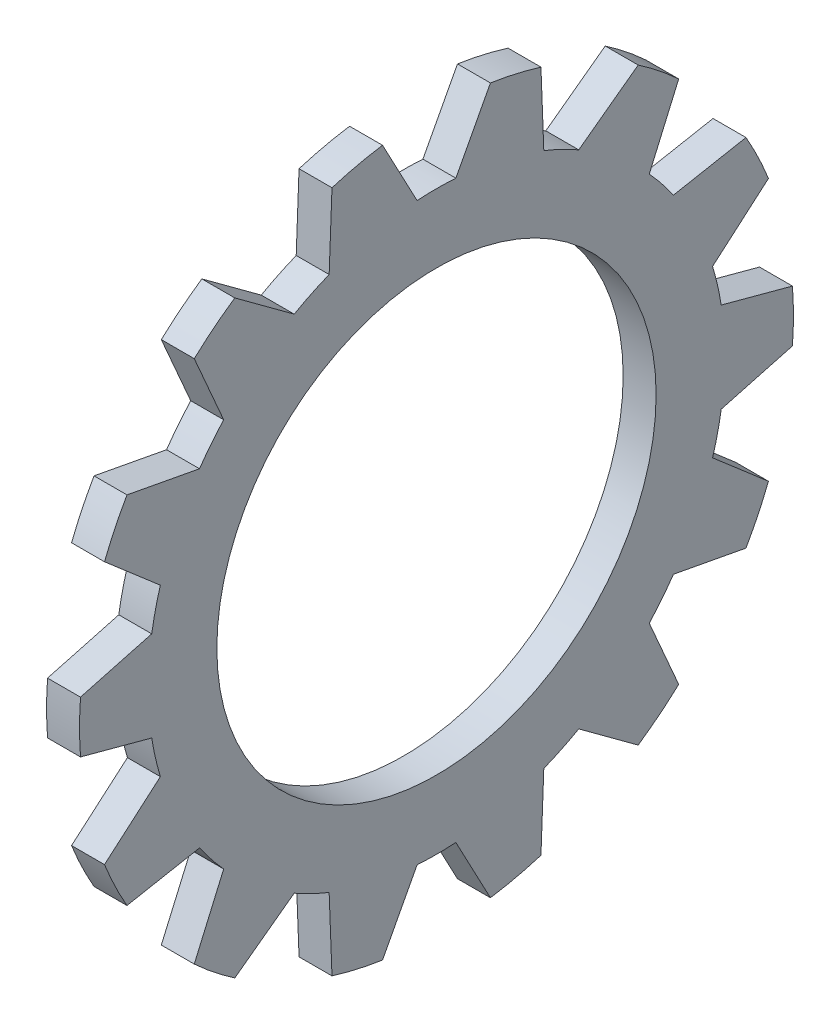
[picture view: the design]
ISO-10303-21;
HEADER;
FILE_DESCRIPTION(('STEP AP214'),'2;1');
FILE_NAME('part.step','',(''),(''),'','','');
FILE_SCHEMA(('AUTOMOTIVE_DESIGN { 1 0 10303 214 1 1 1 1 }'));
ENDSEC;
DATA;
#1=APPLICATION_CONTEXT('core data for automotive mechanical design processes');
#2=APPLICATION_PROTOCOL_DEFINITION('international standard','automotive_design',2000,#1);
#3=PRODUCT_CONTEXT('',#1,'mechanical');
#4=PRODUCT('Part','Part','',(#3));
#5=PRODUCT_RELATED_PRODUCT_CATEGORY('part','',(#4));
#6=PRODUCT_DEFINITION_FORMATION('','',#4);
#7=PRODUCT_DEFINITION_CONTEXT('part definition',#1,'design');
#8=PRODUCT_DEFINITION('design','',#6,#7);
#9=PRODUCT_DEFINITION_SHAPE('','',#8);
#10=(LENGTH_UNIT() NAMED_UNIT(*) SI_UNIT(.MILLI.,.METRE.));
#11=(NAMED_UNIT(*) PLANE_ANGLE_UNIT() SI_UNIT($,.RADIAN.));
#12=(NAMED_UNIT(*) SI_UNIT($,.STERADIAN.) SOLID_ANGLE_UNIT());
#13=UNCERTAINTY_MEASURE_WITH_UNIT(LENGTH_MEASURE(1.E-05),#10,'distance_accuracy_value','');
#14=(GEOMETRIC_REPRESENTATION_CONTEXT(3) GLOBAL_UNCERTAINTY_ASSIGNED_CONTEXT((#13)) GLOBAL_UNIT_ASSIGNED_CONTEXT((#10,
#11,#12)) REPRESENTATION_CONTEXT('',''));
#15=CARTESIAN_POINT('',(0.,0.,0.));
#16=DIRECTION('',(0.,0.,1.));
#17=DIRECTION('',(1.,0.,0.));
#18=AXIS2_PLACEMENT_3D('',#15,#16,#17);
#19=CARTESIAN_POINT('',(-34.9249999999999,0.,0.));
#20=DIRECTION('',(-1.,0.,0.));
#21=DIRECTION('',(0.,0.,1.));
#22=AXIS2_PLACEMENT_3D('',#19,#20,#21);
#23=CYLINDRICAL_SURFACE('',#22,13.);
#24=CARTESIAN_POINT('',(-1.2,0.,0.));
#25=DIRECTION('',(-1.,0.,0.));
#26=DIRECTION('',(0.,0.,1.));
#27=AXIS2_PLACEMENT_3D('',#24,#25,#26);
#28=CIRCLE('',#27,13.);
#29=CARTESIAN_POINT('',(-1.2,9.54851327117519,8.82189856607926));
#30=VERTEX_POINT('',#29);
#31=CARTESIAN_POINT('',(-1.2,10.7254592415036,7.34605499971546));
#32=VERTEX_POINT('',#31);
#33=EDGE_CURVE('E754',#30,#32,#28,.T.);
#34=ORIENTED_EDGE('',*,*,#33,.F.);
#35=DIRECTION('',(-1.,0.,0.));
#36=VECTOR('',#35,1.);
#37=CARTESIAN_POINT('',(-34.9249999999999,9.54851327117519,8.82189856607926));
#38=LINE('',#37,#36);
#39=CARTESIAN_POINT('',(0.,9.54851327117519,8.82189856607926));
#40=VERTEX_POINT('',#39);
#41=EDGE_CURVE('E686',#30,#40,#38,.F.);
#42=ORIENTED_EDGE('',*,*,#41,.T.);
#43=CARTESIAN_POINT('',(0.,0.,0.));
#44=DIRECTION('',(-1.,0.,0.));
#45=DIRECTION('',(0.,0.,1.));
#46=AXIS2_PLACEMENT_3D('',#43,#44,#45);
#47=CIRCLE('',#46,13.);
#48=CARTESIAN_POINT('',(0.,10.7254592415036,7.34605499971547));
#49=VERTEX_POINT('',#48);
#50=EDGE_CURVE('E748',#40,#49,#47,.T.);
#51=ORIENTED_EDGE('',*,*,#50,.T.);
#52=DIRECTION('',(-1.,0.,0.));
#53=VECTOR('',#52,1.);
#54=CARTESIAN_POINT('',(-34.9249999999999,10.7254592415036,7.34605499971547));
#55=LINE('',#54,#53);
#56=EDGE_CURVE('E706',#49,#32,#55,.T.);
#57=ORIENTED_EDGE('',*,*,#56,.T.);
#58=EDGE_LOOP('',(#34,#42,#51,#57));
#59=FACE_BOUND('',#58,.T.);
#60=ADVANCED_FACE('F32',(#59),#23,.T.);
#61=CARTESIAN_POINT('',(0.,4.77523485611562,12.0912006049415));
#62=VERTEX_POINT('',#61);
#63=CARTESIAN_POINT('',(0.,6.47597105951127,11.2721692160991));
#64=VERTEX_POINT('',#63);
#65=EDGE_CURVE('E807',#62,#64,#47,.T.);
#66=ORIENTED_EDGE('',*,*,#65,.T.);
#67=DIRECTION('',(-1.,0.,0.));
#68=VECTOR('',#67,1.);
#69=CARTESIAN_POINT('',(-34.9249999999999,6.47597105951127,11.2721692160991));
#70=LINE('',#69,#68);
#71=CARTESIAN_POINT('',(-1.2,6.47597105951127,11.2721692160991));
#72=VERTEX_POINT('',#71);
#73=EDGE_CURVE('E47',#64,#72,#70,.T.);
#74=ORIENTED_EDGE('',*,*,#73,.T.);
#75=CARTESIAN_POINT('',(-1.2,4.77523485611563,12.0912006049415));
#76=VERTEX_POINT('',#75);
#77=EDGE_CURVE('E404',#76,#72,#28,.T.);
#78=ORIENTED_EDGE('',*,*,#77,.F.);
#79=DIRECTION('',(-1.,0.,0.));
#80=VECTOR('',#79,1.);
#81=CARTESIAN_POINT('',(-34.9249999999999,4.77523485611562,12.0912006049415));
#82=LINE('',#81,#80);
#83=EDGE_CURVE('E682',#76,#62,#82,.F.);
#84=ORIENTED_EDGE('',*,*,#83,.T.);
#85=EDGE_LOOP('',(#66,#74,#78,#84));
#86=FACE_BOUND('',#85,.T.);
#87=ADVANCED_FACE('F922',(#86),#23,.T.);
#88=CARTESIAN_POINT('',(0.,-0.943837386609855,12.9656920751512));
#89=VERTEX_POINT('',#88);
#90=CARTESIAN_POINT('',(0.,0.943837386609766,12.9656920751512));
#91=VERTEX_POINT('',#90);
#92=EDGE_CURVE('E800',#89,#91,#47,.T.);
#93=ORIENTED_EDGE('',*,*,#92,.T.);
#94=DIRECTION('',(-1.,0.,0.));
#95=VECTOR('',#94,1.);
#96=CARTESIAN_POINT('',(-34.9249999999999,0.943837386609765,12.9656920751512));
#97=LINE('',#96,#95);
#98=CARTESIAN_POINT('',(-1.2,0.943837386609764,12.9656920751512));
#99=VERTEX_POINT('',#98);
#100=EDGE_CURVE('E54',#91,#99,#97,.T.);
#101=ORIENTED_EDGE('',*,*,#100,.T.);
#102=CARTESIAN_POINT('',(-1.2,-0.943837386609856,12.9656920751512));
#103=VERTEX_POINT('',#102);
#104=EDGE_CURVE('E868',#103,#99,#28,.T.);
#105=ORIENTED_EDGE('',*,*,#104,.F.);
#106=DIRECTION('',(-1.,0.,0.));
#107=VECTOR('',#106,1.);
#108=CARTESIAN_POINT('',(-34.9249999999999,-0.943837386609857,12.9656920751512));
#109=LINE('',#108,#107);
#110=EDGE_CURVE('E678',#103,#89,#109,.F.);
#111=ORIENTED_EDGE('',*,*,#110,.T.);
#112=EDGE_LOOP('',(#93,#101,#105,#111));
#113=FACE_BOUND('',#112,.T.);
#114=ADVANCED_FACE('F803',(#113),#23,.T.);
#115=CARTESIAN_POINT('',(-1.2,-12.8506386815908,1.96496449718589));
#116=VERTEX_POINT('',#115);
#117=CARTESIAN_POINT('',(-1.2,-12.4305915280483,3.80531132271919));
#118=VERTEX_POINT('',#117);
#119=EDGE_CURVE('E863',#116,#118,#28,.T.);
#120=ORIENTED_EDGE('',*,*,#119,.F.);
#121=DIRECTION('',(-1.,0.,0.));
#122=VECTOR('',#121,1.);
#123=CARTESIAN_POINT('',(-34.9249999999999,-12.8506386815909,1.96496449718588));
#124=LINE('',#123,#122);
#125=CARTESIAN_POINT('',(0.,-12.8506386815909,1.96496449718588));
#126=VERTEX_POINT('',#125);
#127=EDGE_CURVE('E672',#116,#126,#124,.F.);
#128=ORIENTED_EDGE('',*,*,#127,.T.);
#129=CARTESIAN_POINT('',(0.,-12.4305915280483,3.80531132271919));
#130=VERTEX_POINT('',#129);
#131=EDGE_CURVE('E839',#126,#130,#47,.T.);
#132=ORIENTED_EDGE('',*,*,#131,.T.);
#133=DIRECTION('',(-1.,0.,0.));
#134=VECTOR('',#133,1.);
#135=CARTESIAN_POINT('',(-34.9249999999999,-12.4305915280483,3.80531132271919));
#136=LINE('',#135,#134);
#137=EDGE_CURVE('E663',#130,#118,#136,.T.);
#138=ORIENTED_EDGE('',*,*,#137,.T.);
#139=EDGE_LOOP('',(#120,#128,#132,#138));
#140=FACE_BOUND('',#139,.T.);
#141=ADVANCED_FACE('F903',(#140),#23,.T.);
#142=CARTESIAN_POINT('',(-1.2,-10.7254592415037,7.34605499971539));
#143=VERTEX_POINT('',#142);
#144=CARTESIAN_POINT('',(-1.2,-9.54851327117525,8.82189856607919));
#145=VERTEX_POINT('',#144);
#146=EDGE_CURVE('E861',#143,#145,#28,.T.);
#147=ORIENTED_EDGE('',*,*,#146,.F.);
#148=DIRECTION('',(-1.,0.,0.));
#149=VECTOR('',#148,1.);
#150=CARTESIAN_POINT('',(-34.9249999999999,-10.7254592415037,7.34605499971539));
#151=LINE('',#150,#149);
#152=CARTESIAN_POINT('',(0.,-10.7254592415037,7.34605499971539));
#153=VERTEX_POINT('',#152);
#154=EDGE_CURVE('E666',#143,#153,#151,.F.);
#155=ORIENTED_EDGE('',*,*,#154,.T.);
#156=CARTESIAN_POINT('',(0.,-9.54851327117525,8.8218985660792));
#157=VERTEX_POINT('',#156);
#158=EDGE_CURVE('E809',#153,#157,#47,.T.);
#159=ORIENTED_EDGE('',*,*,#158,.T.);
#160=DIRECTION('',(-1.,0.,0.));
#161=VECTOR('',#160,1.);
#162=CARTESIAN_POINT('',(-34.9249999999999,-9.54851327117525,8.8218985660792));
#163=LINE('',#162,#161);
#164=EDGE_CURVE('E657',#157,#145,#163,.T.);
#165=ORIENTED_EDGE('',*,*,#164,.T.);
#166=EDGE_LOOP('',(#147,#155,#159,#165));
#167=FACE_BOUND('',#166,.T.);
#168=ADVANCED_FACE('F849',(#167),#23,.T.);
#169=CARTESIAN_POINT('',(0.,-6.47597105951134,11.2721692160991));
#170=VERTEX_POINT('',#169);
#171=CARTESIAN_POINT('',(0.,-4.77523485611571,12.0912006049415));
#172=VERTEX_POINT('',#171);
#173=EDGE_CURVE('E806',#170,#172,#47,.T.);
#174=ORIENTED_EDGE('',*,*,#173,.T.);
#175=DIRECTION('',(-1.,0.,0.));
#176=VECTOR('',#175,1.);
#177=CARTESIAN_POINT('',(-34.9249999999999,-4.77523485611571,12.0912006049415));
#178=LINE('',#177,#176);
#179=CARTESIAN_POINT('',(-1.2,-4.77523485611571,12.0912006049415));
#180=VERTEX_POINT('',#179);
#181=EDGE_CURVE('E675',#172,#180,#178,.T.);
#182=ORIENTED_EDGE('',*,*,#181,.T.);
#183=CARTESIAN_POINT('',(-1.2,-6.47597105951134,11.2721692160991));
#184=VERTEX_POINT('',#183);
#185=EDGE_CURVE('E864',#184,#180,#28,.T.);
#186=ORIENTED_EDGE('',*,*,#185,.F.);
#187=DIRECTION('',(-1.,0.,0.));
#188=VECTOR('',#187,1.);
#189=CARTESIAN_POINT('',(-34.9249999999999,-6.47597105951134,11.2721692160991));
#190=LINE('',#189,#188);
#191=EDGE_CURVE('E660',#184,#170,#190,.F.);
#192=ORIENTED_EDGE('',*,*,#191,.T.);
#193=EDGE_LOOP('',(#174,#182,#186,#192));
#194=FACE_BOUND('',#193,.T.);
#195=ADVANCED_FACE('F1348',(#194),#23,.T.);
#196=CARTESIAN_POINT('',(-1.2,-4.77523485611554,-12.0912006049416));
#197=VERTEX_POINT('',#196);
#198=CARTESIAN_POINT('',(-1.2,-6.47597105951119,-11.2721692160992));
#199=VERTEX_POINT('',#198);
#200=EDGE_CURVE('E881',#197,#199,#28,.T.);
#201=ORIENTED_EDGE('',*,*,#200,.F.);
#202=DIRECTION('',(-1.,0.,0.));
#203=VECTOR('',#202,1.);
#204=CARTESIAN_POINT('',(-34.9249999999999,-4.77523485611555,-12.0912006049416));
#205=LINE('',#204,#203);
#206=CARTESIAN_POINT('',(0.,-4.77523485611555,-12.0912006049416));
#207=VERTEX_POINT('',#206);
#208=EDGE_CURVE('E654',#197,#207,#205,.F.);
#209=ORIENTED_EDGE('',*,*,#208,.T.);
#210=CARTESIAN_POINT('',(0.,-6.47597105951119,-11.2721692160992));
#211=VERTEX_POINT('',#210);
#212=EDGE_CURVE('E827',#207,#211,#47,.T.);
#213=ORIENTED_EDGE('',*,*,#212,.T.);
#214=DIRECTION('',(-1.,0.,0.));
#215=VECTOR('',#214,1.);
#216=CARTESIAN_POINT('',(-34.9249999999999,-6.47597105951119,-11.2721692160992));
#217=LINE('',#216,#215);
#218=EDGE_CURVE('E645',#211,#199,#217,.T.);
#219=ORIENTED_EDGE('',*,*,#218,.T.);
#220=EDGE_LOOP('',(#201,#209,#213,#219));
#221=FACE_BOUND('',#220,.T.);
#222=ADVANCED_FACE('F995',(#221),#23,.T.);
#223=CARTESIAN_POINT('',(-1.2,-9.54851327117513,-8.82189856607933));
#224=VERTEX_POINT('',#223);
#225=CARTESIAN_POINT('',(-1.2,-10.7254592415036,-7.34605499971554));
#226=VERTEX_POINT('',#225);
#227=EDGE_CURVE('E884',#224,#226,#28,.T.);
#228=ORIENTED_EDGE('',*,*,#227,.F.);
#229=DIRECTION('',(-1.,0.,0.));
#230=VECTOR('',#229,1.);
#231=CARTESIAN_POINT('',(-34.9249999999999,-9.54851327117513,-8.82189856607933));
#232=LINE('',#231,#230);
#233=CARTESIAN_POINT('',(0.,-9.54851327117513,-8.82189856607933));
#234=VERTEX_POINT('',#233);
#235=EDGE_CURVE('E648',#224,#234,#232,.F.);
#236=ORIENTED_EDGE('',*,*,#235,.T.);
#237=CARTESIAN_POINT('',(0.,-10.7254592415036,-7.34605499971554));
#238=VERTEX_POINT('',#237);
#239=EDGE_CURVE('E831',#234,#238,#47,.T.);
#240=ORIENTED_EDGE('',*,*,#239,.T.);
#241=DIRECTION('',(-1.,0.,0.));
#242=VECTOR('',#241,1.);
#243=CARTESIAN_POINT('',(-34.9249999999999,-10.7254592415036,-7.34605499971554));
#244=LINE('',#243,#242);
#245=EDGE_CURVE('E639',#238,#226,#244,.T.);
#246=ORIENTED_EDGE('',*,*,#245,.T.);
#247=EDGE_LOOP('',(#228,#236,#240,#246));
#248=FACE_BOUND('',#247,.T.);
#249=ADVANCED_FACE('F1005',(#248),#23,.T.);
#250=CARTESIAN_POINT('',(0.,-12.4305915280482,-3.80531132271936));
#251=VERTEX_POINT('',#250);
#252=CARTESIAN_POINT('',(0.,-12.8506386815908,-1.96496449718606));
#253=VERTEX_POINT('',#252);
#254=EDGE_CURVE('E835',#251,#253,#47,.T.);
#255=ORIENTED_EDGE('',*,*,#254,.T.);
#256=DIRECTION('',(-1.,0.,0.));
#257=VECTOR('',#256,1.);
#258=CARTESIAN_POINT('',(-34.9249999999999,-12.8506386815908,-1.96496449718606));
#259=LINE('',#258,#257);
#260=CARTESIAN_POINT('',(-1.2,-12.8506386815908,-1.96496449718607));
#261=VERTEX_POINT('',#260);
#262=EDGE_CURVE('E669',#253,#261,#259,.T.);
#263=ORIENTED_EDGE('',*,*,#262,.T.);
#264=CARTESIAN_POINT('',(-1.2,-12.4305915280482,-3.80531132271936));
#265=VERTEX_POINT('',#264);
#266=EDGE_CURVE('E866',#265,#261,#28,.T.);
#267=ORIENTED_EDGE('',*,*,#266,.F.);
#268=DIRECTION('',(-1.,0.,0.));
#269=VECTOR('',#268,1.);
#270=CARTESIAN_POINT('',(-34.9249999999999,-12.4305915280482,-3.80531132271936));
#271=LINE('',#270,#269);
#272=EDGE_CURVE('E642',#265,#251,#271,.F.);
#273=ORIENTED_EDGE('',*,*,#272,.T.);
#274=EDGE_LOOP('',(#255,#263,#267,#273));
#275=FACE_BOUND('',#274,.T.);
#276=ADVANCED_FACE('F891',(#275),#23,.T.);
#277=CARTESIAN_POINT('',(0.,0.94383738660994,-12.9656920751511));
#278=VERTEX_POINT('',#277);
#279=CARTESIAN_POINT('',(0.,-0.94383738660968,-12.9656920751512));
#280=VERTEX_POINT('',#279);
#281=EDGE_CURVE('E823',#278,#280,#47,.T.);
#282=ORIENTED_EDGE('',*,*,#281,.T.);
#283=DIRECTION('',(-1.,0.,0.));
#284=VECTOR('',#283,1.);
#285=CARTESIAN_POINT('',(-34.9249999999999,-0.94383738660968,-12.9656920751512));
#286=LINE('',#285,#284);
#287=CARTESIAN_POINT('',(-1.2,-0.943837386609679,-12.9656920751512));
#288=VERTEX_POINT('',#287);
#289=EDGE_CURVE('E651',#280,#288,#286,.T.);
#290=ORIENTED_EDGE('',*,*,#289,.T.);
#291=CARTESIAN_POINT('',(-1.2,0.94383738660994,-12.9656920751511));
#292=VERTEX_POINT('',#291);
#293=EDGE_CURVE('E878',#292,#288,#28,.T.);
#294=ORIENTED_EDGE('',*,*,#293,.F.);
#295=DIRECTION('',(-1.,0.,0.));
#296=VECTOR('',#295,1.);
#297=CARTESIAN_POINT('',(-34.9249999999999,0.94383738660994,-12.9656920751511));
#298=LINE('',#297,#296);
#299=EDGE_CURVE('E636',#292,#278,#298,.F.);
#300=ORIENTED_EDGE('',*,*,#299,.T.);
#301=EDGE_LOOP('',(#282,#290,#294,#300));
#302=FACE_BOUND('',#301,.T.);
#303=ADVANCED_FACE('F985',(#302),#23,.T.);
#304=CARTESIAN_POINT('',(-1.2,10.7254592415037,-7.34605499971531));
#305=VERTEX_POINT('',#304);
#306=CARTESIAN_POINT('',(-1.2,9.54851327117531,-8.82189856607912));
#307=VERTEX_POINT('',#306);
#308=EDGE_CURVE('E753',#305,#307,#28,.T.);
#309=ORIENTED_EDGE('',*,*,#308,.F.);
#310=DIRECTION('',(-1.,0.,0.));
#311=VECTOR('',#310,1.);
#312=CARTESIAN_POINT('',(-34.9249999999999,10.7254592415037,-7.34605499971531));
#313=LINE('',#312,#311);
#314=CARTESIAN_POINT('',(0.,10.7254592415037,-7.34605499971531));
#315=VERTEX_POINT('',#314);
#316=EDGE_CURVE('E630',#305,#315,#313,.F.);
#317=ORIENTED_EDGE('',*,*,#316,.T.);
#318=CARTESIAN_POINT('',(0.,9.54851327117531,-8.82189856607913));
#319=VERTEX_POINT('',#318);
#320=EDGE_CURVE('E747',#315,#319,#47,.T.);
#321=ORIENTED_EDGE('',*,*,#320,.T.);
#322=DIRECTION('',(-1.,0.,0.));
#323=VECTOR('',#322,1.);
#324=CARTESIAN_POINT('',(-34.9249999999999,9.54851327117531,-8.82189856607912));
#325=LINE('',#324,#323);
#326=EDGE_CURVE('E413',#319,#307,#325,.T.);
#327=ORIENTED_EDGE('',*,*,#326,.T.);
#328=EDGE_LOOP('',(#309,#317,#321,#327));
#329=FACE_BOUND('',#328,.T.);
#330=ADVANCED_FACE('F945',(#329),#23,.T.);
#331=CARTESIAN_POINT('',(0.,6.47597105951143,-11.272169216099));
#332=VERTEX_POINT('',#331);
#333=CARTESIAN_POINT('',(0.,4.77523485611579,-12.0912006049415));
#334=VERTEX_POINT('',#333);
#335=EDGE_CURVE('E819',#332,#334,#47,.T.);
#336=ORIENTED_EDGE('',*,*,#335,.T.);
#337=DIRECTION('',(-1.,0.,0.));
#338=VECTOR('',#337,1.);
#339=CARTESIAN_POINT('',(-34.9249999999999,4.77523485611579,-12.0912006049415));
#340=LINE('',#339,#338);
#341=CARTESIAN_POINT('',(-1.2,4.77523485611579,-12.0912006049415));
#342=VERTEX_POINT('',#341);
#343=EDGE_CURVE('E633',#334,#342,#340,.T.);
#344=ORIENTED_EDGE('',*,*,#343,.T.);
#345=CARTESIAN_POINT('',(-1.2,6.47597105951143,-11.272169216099));
#346=VERTEX_POINT('',#345);
#347=EDGE_CURVE('E875',#346,#342,#28,.T.);
#348=ORIENTED_EDGE('',*,*,#347,.F.);
#349=DIRECTION('',(-1.,0.,0.));
#350=VECTOR('',#349,1.);
#351=CARTESIAN_POINT('',(-34.9249999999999,6.47597105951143,-11.272169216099));
#352=LINE('',#351,#350);
#353=EDGE_CURVE('E624',#346,#332,#352,.F.);
#354=ORIENTED_EDGE('',*,*,#353,.T.);
#355=EDGE_LOOP('',(#336,#344,#348,#354));
#356=FACE_BOUND('',#355,.T.);
#357=ADVANCED_FACE('F939',(#356),#23,.T.);
#358=CARTESIAN_POINT('',(-1.2,12.4305915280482,3.80531132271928));
#359=VERTEX_POINT('',#358);
#360=CARTESIAN_POINT('',(-1.2,12.8506386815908,1.96496449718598));
#361=VERTEX_POINT('',#360);
#362=EDGE_CURVE('E746',#359,#361,#28,.T.);
#363=ORIENTED_EDGE('',*,*,#362,.F.);
#364=DIRECTION('',(-1.,0.,0.));
#365=VECTOR('',#364,1.);
#366=CARTESIAN_POINT('',(-34.9249999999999,12.4305915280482,3.80531132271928));
#367=LINE('',#366,#365);
#368=CARTESIAN_POINT('',(0.,12.4305915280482,3.80531132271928));
#369=VERTEX_POINT('',#368);
#370=EDGE_CURVE('E711',#359,#369,#367,.F.);
#371=ORIENTED_EDGE('',*,*,#370,.T.);
#372=CARTESIAN_POINT('',(0.,12.8506386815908,1.96496449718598));
#373=VERTEX_POINT('',#372);
#374=EDGE_CURVE('E742',#369,#373,#47,.T.);
#375=ORIENTED_EDGE('',*,*,#374,.T.);
#376=DIRECTION('',(-1.,0.,0.));
#377=VECTOR('',#376,1.);
#378=CARTESIAN_POINT('',(-34.9249999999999,12.8506386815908,1.96496449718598));
#379=LINE('',#378,#377);
#380=EDGE_CURVE('E731',#373,#361,#379,.T.);
#381=ORIENTED_EDGE('',*,*,#380,.T.);
#382=EDGE_LOOP('',(#363,#371,#375,#381));
#383=FACE_BOUND('',#382,.T.);
#384=ADVANCED_FACE('F931',(#383),#23,.T.);
#385=CARTESIAN_POINT('',(-34.9249999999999,0.,0.));
#386=DIRECTION('',(-1.,0.,0.));
#387=DIRECTION('',(0.,0.,1.));
#388=AXIS2_PLACEMENT_3D('',#385,#386,#387);
#389=CYLINDRICAL_SURFACE('',#388,8.);
#390=CARTESIAN_POINT('',(0.,0.,0.));
#391=DIRECTION('',(-1.,0.,0.));
#392=DIRECTION('',(0.,0.,1.));
#393=AXIS2_PLACEMENT_3D('',#390,#391,#392);
#394=CIRCLE('',#393,8.);
#395=CARTESIAN_POINT('',(0.,0.,8.));
#396=VERTEX_POINT('',#395);
#397=EDGE_CURVE('E739',#396,#396,#394,.T.);
#398=ORIENTED_EDGE('',*,*,#397,.F.);
#399=EDGE_LOOP('',(#398));
#400=FACE_BOUND('',#399,.T.);
#401=CARTESIAN_POINT('',(-1.2,0.,0.));
#402=DIRECTION('',(-1.,0.,0.));
#403=DIRECTION('',(0.,0.,1.));
#404=AXIS2_PLACEMENT_3D('',#401,#402,#403);
#405=CIRCLE('',#404,8.);
#406=CARTESIAN_POINT('',(-1.2,0.,8.));
#407=VERTEX_POINT('',#406);
#408=EDGE_CURVE('E752',#407,#407,#405,.T.);
#409=ORIENTED_EDGE('',*,*,#408,.T.);
#410=EDGE_LOOP('',(#409));
#411=FACE_BOUND('',#410,.T.);
#412=ADVANCED_FACE('F34',(#400,#411),#389,.F.);
#413=CARTESIAN_POINT('',(-1.2,13.,0.));
#414=DIRECTION('',(1.,0.,0.));
#415=DIRECTION('',(0.,0.,-1.));
#416=AXIS2_PLACEMENT_3D('',#413,#414,#415);
#417=PLANE('',#416);
#418=ORIENTED_EDGE('',*,*,#408,.F.);
#419=EDGE_LOOP('',(#418));
#420=FACE_BOUND('',#419,.T.);
#421=CARTESIAN_POINT('',(-1.2,0.,0.));
#422=DIRECTION('',(-1.,0.,0.));
#423=DIRECTION('',(0.,0.781831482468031,-0.623489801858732));
#424=AXIS2_PLACEMENT_3D('',#421,#422,#423);
#425=CIRCLE('',#424,10.5);
#426=CARTESIAN_POINT('',(-1.2,5.97958717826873,8.63102179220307));
#427=VERTEX_POINT('',#426);
#428=CARTESIAN_POINT('',(-1.2,7.08404073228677,7.75024947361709));
#429=VERTEX_POINT('',#428);
#430=EDGE_CURVE('E394',#427,#429,#425,.T.);
#431=ORIENTED_EDGE('',*,*,#430,.T.);
#432=DIRECTION('',(0.,0.917051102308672,0.398769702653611));
#433=VECTOR('',#432,1.);
#434=CARTESIAN_POINT('',(-1.2,10.1780155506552,9.09563078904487));
#435=LINE('',#434,#433);
#436=EDGE_CURVE('E391',#429,#30,#435,.T.);
#437=ORIENTED_EDGE('',*,*,#436,.T.);
#438=ORIENTED_EDGE('',*,*,#33,.T.);
#439=DIRECTION('',(0.,-0.592834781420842,-0.805324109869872));
#440=VECTOR('',#439,1.);
#441=CARTESIAN_POINT('',(-1.2,11.1324058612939,7.89886319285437));
#442=LINE('',#441,#440);
#443=CARTESIAN_POINT('',(-1.2,9.13228189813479,5.18183628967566));
#444=VERTEX_POINT('',#443);
#445=EDGE_CURVE('E690',#32,#444,#442,.T.);
#446=ORIENTED_EDGE('',*,*,#445,.T.);
#447=CARTESIAN_POINT('',(-1.2,0.,0.));
#448=DIRECTION('',(-1.,0.,0.));
#449=DIRECTION('',(0.,0.433883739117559,-0.900968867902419));
#450=AXIS2_PLACEMENT_3D('',#447,#448,#449);
#451=CIRCLE('',#450,10.5);
#452=CARTESIAN_POINT('',(-1.2,9.74520737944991,3.90908341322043));
#453=VERTEX_POINT('',#452);
#454=EDGE_CURVE('E693',#444,#453,#451,.T.);
#455=ORIENTED_EDGE('',*,*,#454,.T.);
#456=DIRECTION('',(0.,0.999254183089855,-0.0386144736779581));
#457=VECTOR('',#456,1.);
#458=CARTESIAN_POINT('',(-1.2,13.1165214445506,3.7788047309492));
#459=LINE('',#458,#457);
#460=EDGE_CURVE('E697',#453,#359,#459,.T.);
#461=ORIENTED_EDGE('',*,*,#460,.T.);
#462=ORIENTED_EDGE('',*,*,#362,.T.);
#463=DIRECTION('',(0.,-0.883542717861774,-0.468350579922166));
#464=VECTOR('',#463,1.);
#465=CARTESIAN_POINT('',(-1.2,13.4571394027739,2.28645994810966));
#466=LINE('',#465,#464);
#467=CARTESIAN_POINT('',(-1.2,10.4762161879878,0.706324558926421));
#468=VERTEX_POINT('',#467);
#469=EDGE_CURVE('E715',#361,#468,#466,.T.);
#470=ORIENTED_EDGE('',*,*,#469,.T.);
#471=CARTESIAN_POINT('',(-1.2,0.,0.));
#472=DIRECTION('',(-1.,0.,0.));
#473=DIRECTION('',(0.,0.,-1.));
#474=AXIS2_PLACEMENT_3D('',#471,#472,#473);
#475=CIRCLE('',#474,10.5);
#476=CARTESIAN_POINT('',(-1.2,10.4762161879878,-0.706324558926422));
#477=VERTEX_POINT('',#476);
#478=EDGE_CURVE('E718',#468,#477,#475,.T.);
#479=ORIENTED_EDGE('',*,*,#478,.T.);
#480=DIRECTION('',(0.,0.883542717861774,-0.468350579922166));
#481=VECTOR('',#480,1.);
#482=CARTESIAN_POINT('',(-1.2,13.4571394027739,-2.28645994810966));
#483=LINE('',#482,#481);
#484=CARTESIAN_POINT('',(-1.2,12.8506386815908,-1.96496449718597));
#485=VERTEX_POINT('',#484);
#486=EDGE_CURVE('E722',#477,#485,#483,.T.);
#487=ORIENTED_EDGE('',*,*,#486,.T.);
#488=CARTESIAN_POINT('',(-1.2,12.4305915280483,-3.8053113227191));
#489=VERTEX_POINT('',#488);
#490=EDGE_CURVE('E749',#485,#489,#28,.T.);
#491=ORIENTED_EDGE('',*,*,#490,.T.);
#492=DIRECTION('',(0.,-0.999254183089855,-0.0386144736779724));
#493=VECTOR('',#492,1.);
#494=CARTESIAN_POINT('',(-1.2,13.1165214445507,-3.77880473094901));
#495=LINE('',#494,#493);
#496=CARTESIAN_POINT('',(-1.2,9.74520737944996,-3.90908341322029));
#497=VERTEX_POINT('',#496);
#498=EDGE_CURVE('E585',#489,#497,#495,.T.);
#499=ORIENTED_EDGE('',*,*,#498,.T.);
#500=CARTESIAN_POINT('',(-1.2,0.,0.));
#501=DIRECTION('',(-1.,0.,0.));
#502=DIRECTION('',(0.,-0.433883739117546,-0.900968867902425));
#503=AXIS2_PLACEMENT_3D('',#500,#501,#502);
#504=CIRCLE('',#503,10.5);
#505=CARTESIAN_POINT('',(-1.2,9.13228189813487,-5.18183628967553));
#506=VERTEX_POINT('',#505);
#507=EDGE_CURVE('E588',#497,#506,#504,.T.);
#508=ORIENTED_EDGE('',*,*,#507,.T.);
#509=DIRECTION('',(0.,0.592834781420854,-0.805324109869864));
#510=VECTOR('',#509,1.);
#511=CARTESIAN_POINT('',(-1.2,11.132405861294,-7.89886319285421));
#512=LINE('',#511,#510);
#513=EDGE_CURVE('E592',#506,#305,#512,.T.);
#514=ORIENTED_EDGE('',*,*,#513,.T.);
#515=ORIENTED_EDGE('',*,*,#308,.T.);
#516=DIRECTION('',(0.,-0.917051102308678,0.398769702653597));
#517=VECTOR('',#516,1.);
#518=CARTESIAN_POINT('',(-1.2,10.1780155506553,-9.09563078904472));
#519=LINE('',#518,#517);
#520=CARTESIAN_POINT('',(-1.2,7.08404073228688,-7.75024947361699));
#521=VERTEX_POINT('',#520);
#522=EDGE_CURVE('E605',#307,#521,#519,.T.);
#523=ORIENTED_EDGE('',*,*,#522,.T.);
#524=CARTESIAN_POINT('',(-1.2,0.,0.));
#525=DIRECTION('',(-1.,0.,0.));
#526=DIRECTION('',(0.,-0.781831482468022,-0.623489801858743));
#527=AXIS2_PLACEMENT_3D('',#524,#525,#526);
#528=CIRCLE('',#527,10.5);
#529=CARTESIAN_POINT('',(-1.2,5.97958717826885,-8.63102179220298));
#530=VERTEX_POINT('',#529);
#531=EDGE_CURVE('E608',#521,#530,#528,.T.);
#532=ORIENTED_EDGE('',*,*,#531,.T.);
#533=DIRECTION('',(0.,0.184708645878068,-0.982793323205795));
#534=VECTOR('',#533,1.);
#535=CARTESIAN_POINT('',(-1.2,6.60276280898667,-11.9467997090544));
#536=LINE('',#535,#534);
#537=EDGE_CURVE('E612',#530,#346,#536,.T.);
#538=ORIENTED_EDGE('',*,*,#537,.T.);
#539=ORIENTED_EDGE('',*,*,#347,.T.);
#540=DIRECTION('',(0.,-0.653214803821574,0.757172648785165));
#541=VECTOR('',#540,1.);
#542=CARTESIAN_POINT('',(-1.2,5.22362885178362,-12.610955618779));
#543=LINE('',#542,#541);
#544=CARTESIAN_POINT('',(-1.2,3.01979293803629,-10.0563835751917));
#545=VERTEX_POINT('',#544);
#546=EDGE_CURVE('E566',#342,#545,#543,.T.);
#547=ORIENTED_EDGE('',*,*,#546,.T.);
#548=CARTESIAN_POINT('',(-1.2,0.,0.));
#549=DIRECTION('',(-1.,0.,0.));
#550=DIRECTION('',(0.,-0.974927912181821,-0.222520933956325));
#551=AXIS2_PLACEMENT_3D('',#548,#549,#550);
#552=CIRCLE('',#551,10.5);
#553=CARTESIAN_POINT('',(-1.2,1.64256188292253,-10.3707275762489));
#554=VERTEX_POINT('',#553);
#555=EDGE_CURVE('E569',#545,#554,#552,.T.);
#556=ORIENTED_EDGE('',*,*,#555,.T.);
#557=DIRECTION('',(0.,-0.260001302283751,-0.965608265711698));
#558=VECTOR('',#557,1.);
#559=CARTESIAN_POINT('',(-1.2,0.765361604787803,-13.6285260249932));
#560=LINE('',#559,#558);
#561=EDGE_CURVE('E573',#554,#292,#560,.T.);
#562=ORIENTED_EDGE('',*,*,#561,.T.);
#563=ORIENTED_EDGE('',*,*,#293,.T.);
#564=DIRECTION('',(0.,-0.260001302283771,0.965608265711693));
#565=VECTOR('',#564,1.);
#566=CARTESIAN_POINT('',(-1.2,-0.765361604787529,-13.6285260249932));
#567=LINE('',#566,#565);
#568=CARTESIAN_POINT('',(-1.2,-1.64256188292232,-10.370727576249));
#569=VERTEX_POINT('',#568);
#570=EDGE_CURVE('E530',#288,#569,#567,.T.);
#571=ORIENTED_EDGE('',*,*,#570,.T.);
#572=CARTESIAN_POINT('',(-1.2,0.,0.));
#573=DIRECTION('',(-1.,0.,0.));
#574=DIRECTION('',(0.,-0.974927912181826,0.222520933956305));
#575=AXIS2_PLACEMENT_3D('',#572,#573,#574);
#576=CIRCLE('',#575,10.5);
#577=CARTESIAN_POINT('',(-1.2,-3.01979293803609,-10.0563835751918));
#578=VERTEX_POINT('',#577);
#579=EDGE_CURVE('E533',#569,#578,#576,.T.);
#580=ORIENTED_EDGE('',*,*,#579,.T.);
#581=DIRECTION('',(0.,-0.653214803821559,-0.757172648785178));
#582=VECTOR('',#581,1.);
#583=CARTESIAN_POINT('',(-1.2,-5.22362885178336,-12.6109556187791));
#584=LINE('',#583,#582);
#585=EDGE_CURVE('E537',#578,#197,#584,.T.);
#586=ORIENTED_EDGE('',*,*,#585,.T.);
#587=ORIENTED_EDGE('',*,*,#200,.T.);
#588=DIRECTION('',(0.,0.184708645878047,0.982793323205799));
#589=VECTOR('',#588,1.);
#590=CARTESIAN_POINT('',(-1.2,-6.60276280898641,-11.9467997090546));
#591=LINE('',#590,#589);
#592=CARTESIAN_POINT('',(-1.2,-5.97958717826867,-8.63102179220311));
#593=VERTEX_POINT('',#592);
#594=EDGE_CURVE('E509',#199,#593,#591,.T.);
#595=ORIENTED_EDGE('',*,*,#594,.T.);
#596=CARTESIAN_POINT('',(-1.2,0.,0.));
#597=DIRECTION('',(-1.,0.,0.));
#598=DIRECTION('',(0.,-0.781831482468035,0.623489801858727));
#599=AXIS2_PLACEMENT_3D('',#596,#597,#598);
#600=CIRCLE('',#599,10.5);
#601=CARTESIAN_POINT('',(-1.2,-7.08404073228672,-7.75024947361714));
#602=VERTEX_POINT('',#601);
#603=EDGE_CURVE('E512',#593,#602,#600,.T.);
#604=ORIENTED_EDGE('',*,*,#603,.T.);
#605=DIRECTION('',(0.,-0.91705110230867,-0.398769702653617));
#606=VECTOR('',#605,1.);
#607=CARTESIAN_POINT('',(-1.2,-10.1780155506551,-9.09563078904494));
#608=LINE('',#607,#606);
#609=EDGE_CURVE('E516',#602,#224,#608,.T.);
#610=ORIENTED_EDGE('',*,*,#609,.T.);
#611=ORIENTED_EDGE('',*,*,#227,.T.);
#612=DIRECTION('',(0.,0.592834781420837,0.805324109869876));
#613=VECTOR('',#612,1.);
#614=CARTESIAN_POINT('',(-1.2,-11.1324058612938,-7.89886319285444));
#615=LINE('',#614,#613);
#616=CARTESIAN_POINT('',(-1.2,-9.13228189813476,-5.18183628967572));
#617=VERTEX_POINT('',#616);
#618=EDGE_CURVE('E549',#226,#617,#615,.T.);
#619=ORIENTED_EDGE('',*,*,#618,.T.);
#620=CARTESIAN_POINT('',(-1.2,0.,0.));
#621=DIRECTION('',(-1.,0.,0.));
#622=DIRECTION('',(0.,-0.433883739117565,0.900968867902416));
#623=AXIS2_PLACEMENT_3D('',#620,#621,#622);
#624=CIRCLE('',#623,10.5);
#625=CARTESIAN_POINT('',(-1.2,-9.74520737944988,-3.9090834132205));
#626=VERTEX_POINT('',#625);
#627=EDGE_CURVE('E552',#617,#626,#624,.T.);
#628=ORIENTED_EDGE('',*,*,#627,.T.);
#629=DIRECTION('',(0.,-0.999254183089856,0.0386144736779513));
#630=VECTOR('',#629,1.);
#631=CARTESIAN_POINT('',(-1.2,-13.1165214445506,-3.77880473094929));
#632=LINE('',#631,#630);
#633=EDGE_CURVE('E556',#626,#265,#632,.T.);
#634=ORIENTED_EDGE('',*,*,#633,.T.);
#635=ORIENTED_EDGE('',*,*,#266,.T.);
#636=DIRECTION('',(0.,0.883542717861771,0.468350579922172));
#637=VECTOR('',#636,1.);
#638=CARTESIAN_POINT('',(-1.2,-13.4571394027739,-2.28645994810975));
#639=LINE('',#638,#637);
#640=CARTESIAN_POINT('',(-1.2,-10.4762161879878,-0.706324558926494));
#641=VERTEX_POINT('',#640);
#642=EDGE_CURVE('E473',#261,#641,#639,.T.);
#643=ORIENTED_EDGE('',*,*,#642,.T.);
#644=CARTESIAN_POINT('',(-1.2,0.,0.));
#645=DIRECTION('',(-1.,0.,0.));
#646=DIRECTION('',(0.,0.,1.));
#647=AXIS2_PLACEMENT_3D('',#644,#645,#646);
#648=CIRCLE('',#647,10.5);
#649=CARTESIAN_POINT('',(-1.2,-10.4762161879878,0.706324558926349));
#650=VERTEX_POINT('',#649);
#651=EDGE_CURVE('E476',#641,#650,#648,.T.);
#652=ORIENTED_EDGE('',*,*,#651,.T.);
#653=DIRECTION('',(0.,-0.883542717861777,0.46835057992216));
#654=VECTOR('',#653,1.);
#655=CARTESIAN_POINT('',(-1.2,-13.4571394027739,2.28645994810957));
#656=LINE('',#655,#654);
#657=EDGE_CURVE('E480',#650,#116,#656,.T.);
#658=ORIENTED_EDGE('',*,*,#657,.T.);
#659=ORIENTED_EDGE('',*,*,#119,.T.);
#660=DIRECTION('',(0.,0.999254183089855,0.0386144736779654));
#661=VECTOR('',#660,1.);
#662=CARTESIAN_POINT('',(-1.2,-13.1165214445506,3.77880473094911));
#663=LINE('',#662,#661);
#664=CARTESIAN_POINT('',(-1.2,-9.74520737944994,3.90908341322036));
#665=VERTEX_POINT('',#664);
#666=EDGE_CURVE('E452',#118,#665,#663,.T.);
#667=ORIENTED_EDGE('',*,*,#666,.T.);
#668=CARTESIAN_POINT('',(-1.2,0.,0.));
#669=DIRECTION('',(-1.,0.,0.));
#670=DIRECTION('',(0.,0.433883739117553,0.900968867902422));
#671=AXIS2_PLACEMENT_3D('',#668,#669,#670);
#672=CIRCLE('',#671,10.5);
#673=CARTESIAN_POINT('',(-1.2,-9.13228189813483,5.18183628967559));
#674=VERTEX_POINT('',#673);
#675=EDGE_CURVE('E455',#665,#674,#672,.T.);
#676=ORIENTED_EDGE('',*,*,#675,.T.);
#677=DIRECTION('',(0.,-0.592834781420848,0.805324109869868));
#678=VECTOR('',#677,1.);
#679=CARTESIAN_POINT('',(-1.2,-11.1324058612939,7.89886319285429));
#680=LINE('',#679,#678);
#681=EDGE_CURVE('E459',#674,#143,#680,.T.);
#682=ORIENTED_EDGE('',*,*,#681,.T.);
#683=ORIENTED_EDGE('',*,*,#146,.T.);
#684=DIRECTION('',(0.,0.917051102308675,-0.398769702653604));
#685=VECTOR('',#684,1.);
#686=CARTESIAN_POINT('',(-1.2,-10.1780155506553,9.0956307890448));
#687=LINE('',#686,#685);
#688=CARTESIAN_POINT('',(-1.2,-7.08404073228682,7.75024947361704));
#689=VERTEX_POINT('',#688);
#690=EDGE_CURVE('E492',#145,#689,#687,.T.);
#691=ORIENTED_EDGE('',*,*,#690,.T.);
#692=CARTESIAN_POINT('',(-1.2,0.,0.));
#693=DIRECTION('',(-1.,0.,0.));
#694=DIRECTION('',(0.,0.781831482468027,0.623489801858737));
#695=AXIS2_PLACEMENT_3D('',#692,#693,#694);
#696=CIRCLE('',#695,10.5);
#697=CARTESIAN_POINT('',(-1.2,-5.97958717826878,8.63102179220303));
#698=VERTEX_POINT('',#697);
#699=EDGE_CURVE('E495',#689,#698,#696,.T.);
#700=ORIENTED_EDGE('',*,*,#699,.T.);
#701=DIRECTION('',(0.,-0.184708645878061,0.982793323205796));
#702=VECTOR('',#701,1.);
#703=CARTESIAN_POINT('',(-1.2,-6.60276280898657,11.9467997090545));
#704=LINE('',#703,#702);
#705=EDGE_CURVE('E499',#698,#184,#704,.T.);
#706=ORIENTED_EDGE('',*,*,#705,.T.);
#707=ORIENTED_EDGE('',*,*,#185,.T.);
#708=DIRECTION('',(0.,0.653214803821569,-0.757172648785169));
#709=VECTOR('',#708,1.);
#710=CARTESIAN_POINT('',(-1.2,-5.22362885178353,12.610955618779));
#711=LINE('',#710,#709);
#712=CARTESIAN_POINT('',(-1.2,-3.01979293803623,10.0563835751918));
#713=VERTEX_POINT('',#712);
#714=EDGE_CURVE('E433',#180,#713,#711,.T.);
#715=ORIENTED_EDGE('',*,*,#714,.T.);
#716=CARTESIAN_POINT('',(-1.2,0.,0.));
#717=DIRECTION('',(-1.,0.,0.));
#718=DIRECTION('',(0.,0.974927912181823,0.222520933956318));
#719=AXIS2_PLACEMENT_3D('',#716,#717,#718);
#720=CIRCLE('',#719,10.5);
#721=CARTESIAN_POINT('',(-1.2,-1.64256188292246,10.3707275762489));
#722=VERTEX_POINT('',#721);
#723=EDGE_CURVE('E436',#713,#722,#720,.T.);
#724=ORIENTED_EDGE('',*,*,#723,.T.);
#725=DIRECTION('',(0.,0.260001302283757,0.965608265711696));
#726=VECTOR('',#725,1.);
#727=CARTESIAN_POINT('',(-1.2,-0.765361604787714,13.6285260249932));
#728=LINE('',#727,#726);
#729=EDGE_CURVE('E440',#722,#103,#728,.T.);
#730=ORIENTED_EDGE('',*,*,#729,.T.);
#731=ORIENTED_EDGE('',*,*,#104,.T.);
#732=DIRECTION('',(0.,0.260001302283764,-0.965608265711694));
#733=VECTOR('',#732,1.);
#734=CARTESIAN_POINT('',(-1.2,0.765361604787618,13.6285260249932));
#735=LINE('',#734,#733);
#736=CARTESIAN_POINT('',(-1.2,1.64256188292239,10.370727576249));
#737=VERTEX_POINT('',#736);
#738=EDGE_CURVE('E415',#99,#737,#735,.T.);
#739=ORIENTED_EDGE('',*,*,#738,.T.);
#740=CARTESIAN_POINT('',(-1.2,0.,0.));
#741=DIRECTION('',(-1.,0.,0.));
#742=DIRECTION('',(0.,0.974927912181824,-0.222520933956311));
#743=AXIS2_PLACEMENT_3D('',#740,#741,#742);
#744=CIRCLE('',#743,10.5);
#745=CARTESIAN_POINT('',(-1.2,3.01979293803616,10.0563835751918));
#746=VERTEX_POINT('',#745);
#747=EDGE_CURVE('E418',#737,#746,#744,.T.);
#748=ORIENTED_EDGE('',*,*,#747,.T.);
#749=DIRECTION('',(0.,0.653214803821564,0.757172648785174));
#750=VECTOR('',#749,1.);
#751=CARTESIAN_POINT('',(-1.2,5.22362885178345,12.6109556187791));
#752=LINE('',#751,#750);
#753=EDGE_CURVE('E422',#746,#76,#752,.T.);
#754=ORIENTED_EDGE('',*,*,#753,.T.);
#755=ORIENTED_EDGE('',*,*,#77,.T.);
#756=DIRECTION('',(0.,-0.184708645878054,-0.982793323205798));
#757=VECTOR('',#756,1.);
#758=CARTESIAN_POINT('',(-1.2,6.60276280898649,11.9467997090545));
#759=LINE('',#758,#757);
#760=EDGE_CURVE('E386',#72,#427,#759,.T.);
#761=ORIENTED_EDGE('',*,*,#760,.T.);
#762=EDGE_LOOP('',(#431,#437,#438,#446,#455,#461,#462,#470,#479,#487,#491,#499,#508,#514,#515,
#523,#532,#538,#539,#547,#556,#562,#563,#571,#580,#586,#587,#595,#604,#610,#611,#619,#628,#634,
#635,#643,#652,#658,#659,#667,#676,#682,#683,#691,#700,#706,#707,#715,#724,#730,#731,#739,#748,
#754,#755,#761));
#763=FACE_BOUND('',#762,.T.);
#764=ADVANCED_FACE('F401',(#420,#763),#417,.F.);
#765=CARTESIAN_POINT('',(0.,12.8506386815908,-1.96496449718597));
#766=VERTEX_POINT('',#765);
#767=CARTESIAN_POINT('',(0.,12.4305915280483,-3.8053113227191));
#768=VERTEX_POINT('',#767);
#769=EDGE_CURVE('E743',#766,#768,#47,.T.);
#770=ORIENTED_EDGE('',*,*,#769,.T.);
#771=DIRECTION('',(-1.,0.,0.));
#772=VECTOR('',#771,1.);
#773=CARTESIAN_POINT('',(-34.9249999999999,12.4305915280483,-3.8053113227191));
#774=LINE('',#773,#772);
#775=EDGE_CURVE('E627',#768,#489,#774,.T.);
#776=ORIENTED_EDGE('',*,*,#775,.T.);
#777=ORIENTED_EDGE('',*,*,#490,.F.);
#778=DIRECTION('',(-1.,0.,0.));
#779=VECTOR('',#778,1.);
#780=CARTESIAN_POINT('',(-34.9249999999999,12.8506386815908,-1.96496449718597));
#781=LINE('',#780,#779);
#782=EDGE_CURVE('E736',#485,#766,#781,.F.);
#783=ORIENTED_EDGE('',*,*,#782,.T.);
#784=EDGE_LOOP('',(#770,#776,#777,#783));
#785=FACE_BOUND('',#784,.T.);
#786=ADVANCED_FACE('F924',(#785),#23,.T.);
#787=CARTESIAN_POINT('',(0.,8.,0.));
#788=DIRECTION('',(-1.,0.,0.));
#789=DIRECTION('',(0.,0.,1.));
#790=AXIS2_PLACEMENT_3D('',#787,#788,#789);
#791=PLANE('',#790);
#792=ORIENTED_EDGE('',*,*,#50,.F.);
#793=DIRECTION('',(0.,0.917051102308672,0.398769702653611));
#794=VECTOR('',#793,1.);
#795=CARTESIAN_POINT('',(0.,10.1780155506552,9.09563078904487));
#796=LINE('',#795,#794);
#797=CARTESIAN_POINT('',(0.,7.08404073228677,7.75024947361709));
#798=VERTEX_POINT('',#797);
#799=EDGE_CURVE('E405',#798,#40,#796,.T.);
#800=ORIENTED_EDGE('',*,*,#799,.F.);
#801=CARTESIAN_POINT('',(0.,0.,0.));
#802=DIRECTION('',(-1.,0.,0.));
#803=DIRECTION('',(0.,0.781831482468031,-0.623489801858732));
#804=AXIS2_PLACEMENT_3D('',#801,#802,#803);
#805=CIRCLE('',#804,10.5);
#806=CARTESIAN_POINT('',(0.,5.97958717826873,8.63102179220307));
#807=VERTEX_POINT('',#806);
#808=EDGE_CURVE('E407',#807,#798,#805,.T.);
#809=ORIENTED_EDGE('',*,*,#808,.F.);
#810=DIRECTION('',(0.,0.184708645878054,0.982793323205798));
#811=VECTOR('',#810,1.);
#812=CARTESIAN_POINT('',(0.,4.48172513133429,0.661233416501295));
#813=LINE('',#812,#811);
#814=EDGE_CURVE('E11',#807,#64,#813,.T.);
#815=ORIENTED_EDGE('',*,*,#814,.T.);
#816=ORIENTED_EDGE('',*,*,#65,.F.);
#817=DIRECTION('',(0.,0.653214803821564,0.757172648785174));
#818=VECTOR('',#817,1.);
#819=CARTESIAN_POINT('',(0.,5.22362885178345,12.6109556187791));
#820=LINE('',#819,#818);
#821=CARTESIAN_POINT('',(0.,3.01979293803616,10.0563835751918));
#822=VERTEX_POINT('',#821);
#823=EDGE_CURVE('E419',#822,#62,#820,.T.);
#824=ORIENTED_EDGE('',*,*,#823,.F.);
#825=CARTESIAN_POINT('',(0.,0.,0.));
#826=DIRECTION('',(-1.,0.,0.));
#827=DIRECTION('',(0.,0.974927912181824,-0.222520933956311));
#828=AXIS2_PLACEMENT_3D('',#825,#826,#827);
#829=CIRCLE('',#828,10.5);
#830=CARTESIAN_POINT('',(0.,1.64256188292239,10.370727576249));
#831=VERTEX_POINT('',#830);
#832=EDGE_CURVE('E425',#831,#822,#829,.T.);
#833=ORIENTED_EDGE('',*,*,#832,.F.);
#834=DIRECTION('',(0.,-0.260001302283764,0.965608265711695));
#835=VECTOR('',#834,1.);
#836=CARTESIAN_POINT('',(0.,4.67599771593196,-0.895026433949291));
#837=LINE('',#836,#835);
#838=EDGE_CURVE('E40',#831,#91,#837,.T.);
#839=ORIENTED_EDGE('',*,*,#838,.T.);
#840=ORIENTED_EDGE('',*,*,#92,.F.);
#841=DIRECTION('',(0.,0.260001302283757,0.965608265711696));
#842=VECTOR('',#841,1.);
#843=CARTESIAN_POINT('',(0.,-0.765361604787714,13.6285260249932));
#844=LINE('',#843,#842);
#845=CARTESIAN_POINT('',(0.,-1.64256188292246,10.3707275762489));
#846=VERTEX_POINT('',#845);
#847=EDGE_CURVE('E437',#846,#89,#844,.T.);
#848=ORIENTED_EDGE('',*,*,#847,.F.);
#849=CARTESIAN_POINT('',(0.,0.,0.));
#850=DIRECTION('',(-1.,0.,0.));
#851=DIRECTION('',(0.,0.974927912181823,0.222520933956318));
#852=AXIS2_PLACEMENT_3D('',#849,#850,#851);
#853=CIRCLE('',#852,10.5);
#854=CARTESIAN_POINT('',(0.,-3.01979293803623,10.0563835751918));
#855=VERTEX_POINT('',#854);
#856=EDGE_CURVE('E444',#855,#846,#853,.T.);
#857=ORIENTED_EDGE('',*,*,#856,.F.);
#858=DIRECTION('',(0.,-0.653214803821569,0.757172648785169));
#859=VECTOR('',#858,1.);
#860=CARTESIAN_POINT('',(0.,6.65608882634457,-1.15939564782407));
#861=LINE('',#860,#859);
#862=EDGE_CURVE('E790',#855,#172,#861,.T.);
#863=ORIENTED_EDGE('',*,*,#862,.T.);
#864=ORIENTED_EDGE('',*,*,#173,.F.);
#865=DIRECTION('',(0.,-0.184708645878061,0.982793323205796));
#866=VECTOR('',#865,1.);
#867=CARTESIAN_POINT('',(0.,-6.60276280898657,11.9467997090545));
#868=LINE('',#867,#866);
#869=CARTESIAN_POINT('',(0.,-5.97958717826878,8.63102179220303));
#870=VERTEX_POINT('',#869);
#871=EDGE_CURVE('E496',#870,#170,#868,.T.);
#872=ORIENTED_EDGE('',*,*,#871,.F.);
#873=CARTESIAN_POINT('',(0.,0.,0.));
#874=DIRECTION('',(-1.,0.,0.));
#875=DIRECTION('',(0.,0.781831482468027,0.623489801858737));
#876=AXIS2_PLACEMENT_3D('',#873,#874,#875);
#877=CIRCLE('',#876,10.5);
#878=CARTESIAN_POINT('',(0.,-7.08404073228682,7.75024947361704));
#879=VERTEX_POINT('',#878);
#880=EDGE_CURVE('E470',#879,#870,#877,.T.);
#881=ORIENTED_EDGE('',*,*,#880,.F.);
#882=DIRECTION('',(0.,-0.917051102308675,0.398769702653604));
#883=VECTOR('',#882,1.);
#884=CARTESIAN_POINT('',(0.,8.43558268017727,1.00170994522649));
#885=LINE('',#884,#883);
#886=EDGE_CURVE('E781',#879,#157,#885,.T.);
#887=ORIENTED_EDGE('',*,*,#886,.T.);
#888=ORIENTED_EDGE('',*,*,#158,.F.);
#889=DIRECTION('',(0.,-0.592834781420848,0.805324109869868));
#890=VECTOR('',#889,1.);
#891=CARTESIAN_POINT('',(0.,-11.1324058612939,7.89886319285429));
#892=LINE('',#891,#890);
#893=CARTESIAN_POINT('',(0.,-9.13228189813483,5.18183628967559));
#894=VERTEX_POINT('',#893);
#895=EDGE_CURVE('E456',#894,#153,#892,.T.);
#896=ORIENTED_EDGE('',*,*,#895,.F.);
#897=CARTESIAN_POINT('',(0.,0.,0.));
#898=DIRECTION('',(-1.,0.,0.));
#899=DIRECTION('',(0.,0.433883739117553,0.900968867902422));
#900=AXIS2_PLACEMENT_3D('',#897,#898,#899);
#901=CIRCLE('',#900,10.5);
#902=CARTESIAN_POINT('',(0.,-9.74520737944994,3.90908341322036));
#903=VERTEX_POINT('',#902);
#904=EDGE_CURVE('E463',#903,#894,#901,.T.);
#905=ORIENTED_EDGE('',*,*,#904,.F.);
#906=DIRECTION('',(0.,-0.999254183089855,-0.0386144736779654));
#907=VECTOR('',#906,1.);
#908=CARTESIAN_POINT('',(0.,7.82270589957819,4.58796545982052));
#909=LINE('',#908,#907);
#910=EDGE_CURVE('E784',#903,#130,#909,.T.);
#911=ORIENTED_EDGE('',*,*,#910,.T.);
#912=ORIENTED_EDGE('',*,*,#131,.F.);
#913=DIRECTION('',(0.,-0.883542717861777,0.46835057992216));
#914=VECTOR('',#913,1.);
#915=CARTESIAN_POINT('',(0.,-13.4571394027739,2.28645994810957));
#916=LINE('',#915,#914);
#917=CARTESIAN_POINT('',(0.,-10.4762161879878,0.706324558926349));
#918=VERTEX_POINT('',#917);
#919=EDGE_CURVE('E477',#918,#126,#916,.T.);
#920=ORIENTED_EDGE('',*,*,#919,.F.);
#921=CARTESIAN_POINT('',(0.,0.,0.));
#922=DIRECTION('',(-1.,0.,0.));
#923=DIRECTION('',(0.,0.,1.));
#924=AXIS2_PLACEMENT_3D('',#921,#922,#923);
#925=CIRCLE('',#924,10.5);
#926=CARTESIAN_POINT('',(0.,-10.4762161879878,-0.706324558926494));
#927=VERTEX_POINT('',#926);
#928=EDGE_CURVE('E484',#927,#918,#925,.T.);
#929=ORIENTED_EDGE('',*,*,#928,.F.);
#930=DIRECTION('',(0.,-0.883542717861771,-0.468350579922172));
#931=VECTOR('',#930,1.);
#932=CARTESIAN_POINT('',(0.,4.23948268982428,7.09421067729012));
#933=LINE('',#932,#931);
#934=EDGE_CURVE('E787',#927,#253,#933,.T.);
#935=ORIENTED_EDGE('',*,*,#934,.T.);
#936=ORIENTED_EDGE('',*,*,#254,.F.);
#937=DIRECTION('',(0.,-0.999254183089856,0.0386144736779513));
#938=VECTOR('',#937,1.);
#939=CARTESIAN_POINT('',(0.,-13.1165214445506,-3.77880473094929));
#940=LINE('',#939,#938);
#941=CARTESIAN_POINT('',(0.,-9.74520737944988,-3.9090834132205));
#942=VERTEX_POINT('',#941);
#943=EDGE_CURVE('E553',#942,#251,#940,.T.);
#944=ORIENTED_EDGE('',*,*,#943,.F.);
#945=CARTESIAN_POINT('',(0.,0.,0.));
#946=DIRECTION('',(-1.,0.,0.));
#947=DIRECTION('',(0.,-0.433883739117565,0.900968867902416));
#948=AXIS2_PLACEMENT_3D('',#945,#946,#947);
#949=CIRCLE('',#948,10.5);
#950=CARTESIAN_POINT('',(0.,-9.13228189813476,-5.18183628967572));
#951=VERTEX_POINT('',#950);
#952=EDGE_CURVE('E527',#951,#942,#949,.T.);
#953=ORIENTED_EDGE('',*,*,#952,.F.);
#954=DIRECTION('',(0.,-0.592834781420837,-0.805324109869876));
#955=VECTOR('',#954,1.);
#956=CARTESIAN_POINT('',(0.,-0.637154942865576,6.35819268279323));
#957=LINE('',#956,#955);
#958=EDGE_CURVE('E772',#951,#238,#957,.T.);
#959=ORIENTED_EDGE('',*,*,#958,.T.);
#960=ORIENTED_EDGE('',*,*,#239,.F.);
#961=DIRECTION('',(0.,-0.91705110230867,-0.398769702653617));
#962=VECTOR('',#961,1.);
#963=CARTESIAN_POINT('',(0.,-10.1780155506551,-9.09563078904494));
#964=LINE('',#963,#962);
#965=CARTESIAN_POINT('',(0.,-7.08404073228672,-7.75024947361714));
#966=VERTEX_POINT('',#965);
#967=EDGE_CURVE('E513',#966,#234,#964,.T.);
#968=ORIENTED_EDGE('',*,*,#967,.F.);
#969=CARTESIAN_POINT('',(0.,0.,0.));
#970=DIRECTION('',(-1.,0.,0.));
#971=DIRECTION('',(0.,-0.781831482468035,0.623489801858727));
#972=AXIS2_PLACEMENT_3D('',#969,#970,#971);
#973=CIRCLE('',#972,10.5);
#974=CARTESIAN_POINT('',(0.,-5.97958717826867,-8.63102179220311));
#975=VERTEX_POINT('',#974);
#976=EDGE_CURVE('E520',#975,#966,#973,.T.);
#977=ORIENTED_EDGE('',*,*,#976,.F.);
#978=DIRECTION('',(0.,-0.184708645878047,-0.982793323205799));
#979=VECTOR('',#978,1.);
#980=CARTESIAN_POINT('',(0.,-3.93584858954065,2.24325336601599));
#981=LINE('',#980,#979);
#982=EDGE_CURVE('E775',#975,#211,#981,.T.);
#983=ORIENTED_EDGE('',*,*,#982,.T.);
#984=ORIENTED_EDGE('',*,*,#212,.F.);
#985=DIRECTION('',(0.,-0.653214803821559,-0.757172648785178));
#986=VECTOR('',#985,1.);
#987=CARTESIAN_POINT('',(0.,-5.22362885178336,-12.6109556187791));
#988=LINE('',#987,#986);
#989=CARTESIAN_POINT('',(0.,-3.01979293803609,-10.0563835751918));
#990=VERTEX_POINT('',#989);
#991=EDGE_CURVE('E534',#990,#207,#988,.T.);
#992=ORIENTED_EDGE('',*,*,#991,.F.);
#993=CARTESIAN_POINT('',(0.,0.,0.));
#994=DIRECTION('',(-1.,0.,0.));
#995=DIRECTION('',(0.,-0.974927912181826,0.222520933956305));
#996=AXIS2_PLACEMENT_3D('',#993,#994,#995);
#997=CIRCLE('',#996,10.5);
#998=CARTESIAN_POINT('',(0.,-1.64256188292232,-10.370727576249));
#999=VERTEX_POINT('',#998);
#1000=EDGE_CURVE('E541',#999,#990,#997,.T.);
#1001=ORIENTED_EDGE('',*,*,#1000,.F.);
#1002=DIRECTION('',(0.,0.260001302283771,-0.965608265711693));
#1003=VECTOR('',#1002,1.);
#1004=CARTESIAN_POINT('',(0.,-3.59438688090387,-3.12192407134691));
#1005=LINE('',#1004,#1003);
#1006=EDGE_CURVE('E778',#999,#280,#1005,.T.);
#1007=ORIENTED_EDGE('',*,*,#1006,.T.);
#1008=ORIENTED_EDGE('',*,*,#281,.F.);
#1009=DIRECTION('',(0.,-0.260001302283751,-0.965608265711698));
#1010=VECTOR('',#1009,1.);
#1011=CARTESIAN_POINT('',(0.,0.765361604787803,-13.6285260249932));
#1012=LINE('',#1011,#1010);
#1013=CARTESIAN_POINT('',(0.,1.64256188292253,-10.3707275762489));
#1014=VERTEX_POINT('',#1013);
#1015=EDGE_CURVE('E570',#1014,#278,#1012,.T.);
#1016=ORIENTED_EDGE('',*,*,#1015,.F.);
#1017=CARTESIAN_POINT('',(0.,0.,0.));
#1018=DIRECTION('',(-1.,0.,0.));
#1019=DIRECTION('',(0.,-0.974927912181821,-0.222520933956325));
#1020=AXIS2_PLACEMENT_3D('',#1017,#1018,#1019);
#1021=CIRCLE('',#1020,10.5);
#1022=CARTESIAN_POINT('',(0.,3.01979293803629,-10.0563835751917));
#1023=VERTEX_POINT('',#1022);
#1024=EDGE_CURVE('E577',#1023,#1014,#1021,.T.);
#1025=ORIENTED_EDGE('',*,*,#1024,.F.);
#1026=DIRECTION('',(0.,0.653214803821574,-0.757172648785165));
#1027=VECTOR('',#1026,1.);
#1028=CARTESIAN_POINT('',(0.,0.170944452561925,-6.75414648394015));
#1029=LINE('',#1028,#1027);
#1030=EDGE_CURVE('E769',#1023,#334,#1029,.T.);
#1031=ORIENTED_EDGE('',*,*,#1030,.T.);
#1032=ORIENTED_EDGE('',*,*,#335,.F.);
#1033=DIRECTION('',(0.,0.184708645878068,-0.982793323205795));
#1034=VECTOR('',#1033,1.);
#1035=CARTESIAN_POINT('',(0.,6.60276280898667,-11.9467997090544));
#1036=LINE('',#1035,#1034);
#1037=CARTESIAN_POINT('',(0.,5.97958717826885,-8.63102179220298));
#1038=VERTEX_POINT('',#1037);
#1039=EDGE_CURVE('E609',#1038,#332,#1036,.T.);
#1040=ORIENTED_EDGE('',*,*,#1039,.F.);
#1041=CARTESIAN_POINT('',(0.,0.,0.));
#1042=DIRECTION('',(-1.,0.,0.));
#1043=DIRECTION('',(0.,-0.781831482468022,-0.623489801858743));
#1044=AXIS2_PLACEMENT_3D('',#1041,#1042,#1043);
#1045=CIRCLE('',#1044,10.5);
#1046=CARTESIAN_POINT('',(0.,7.08404073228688,-7.75024947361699));
#1047=VERTEX_POINT('',#1046);
#1048=EDGE_CURVE('E602',#1047,#1038,#1045,.T.);
#1049=ORIENTED_EDGE('',*,*,#1048,.F.);
#1050=DIRECTION('',(0.,0.917051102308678,-0.398769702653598));
#1051=VECTOR('',#1050,1.);
#1052=CARTESIAN_POINT('',(0.,5.02014090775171,-6.85278507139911));
#1053=LINE('',#1052,#1051);
#1054=EDGE_CURVE('E763',#1047,#319,#1053,.T.);
#1055=ORIENTED_EDGE('',*,*,#1054,.T.);
#1056=ORIENTED_EDGE('',*,*,#320,.F.);
#1057=DIRECTION('',(0.,0.592834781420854,-0.805324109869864));
#1058=VECTOR('',#1057,1.);
#1059=CARTESIAN_POINT('',(0.,11.132405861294,-7.89886319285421));
#1060=LINE('',#1059,#1058);
#1061=CARTESIAN_POINT('',(0.,9.13228189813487,-5.18183628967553));
#1062=VERTEX_POINT('',#1061);
#1063=EDGE_CURVE('E589',#1062,#315,#1060,.T.);
#1064=ORIENTED_EDGE('',*,*,#1063,.F.);
#1065=CARTESIAN_POINT('',(0.,0.,0.));
#1066=DIRECTION('',(-1.,0.,0.));
#1067=DIRECTION('',(0.,-0.433883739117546,-0.900968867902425));
#1068=AXIS2_PLACEMENT_3D('',#1065,#1066,#1067);
#1069=CIRCLE('',#1068,10.5);
#1070=CARTESIAN_POINT('',(0.,9.74520737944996,-3.90908341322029));
#1071=VERTEX_POINT('',#1070);
#1072=EDGE_CURVE('E596',#1071,#1062,#1069,.T.);
#1073=ORIENTED_EDGE('',*,*,#1072,.F.);
#1074=DIRECTION('',(0.,0.999254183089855,0.0386144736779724));
#1075=VECTOR('',#1074,1.);
#1076=CARTESIAN_POINT('',(0.,8.15343685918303,-3.97059467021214));
#1077=LINE('',#1076,#1075);
#1078=EDGE_CURVE('E766',#1071,#768,#1077,.T.);
#1079=ORIENTED_EDGE('',*,*,#1078,.T.);
#1080=ORIENTED_EDGE('',*,*,#769,.F.);
#1081=DIRECTION('',(0.,0.883542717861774,-0.468350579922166));
#1082=VECTOR('',#1081,1.);
#1083=CARTESIAN_POINT('',(0.,13.4571394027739,-2.28645994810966));
#1084=LINE('',#1083,#1082);
#1085=CARTESIAN_POINT('',(0.,10.4762161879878,-0.706324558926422));
#1086=VERTEX_POINT('',#1085);
#1087=EDGE_CURVE('E719',#1086,#766,#1084,.T.);
#1088=ORIENTED_EDGE('',*,*,#1087,.F.);
#1089=CARTESIAN_POINT('',(0.,0.,0.));
#1090=DIRECTION('',(-1.,0.,0.));
#1091=DIRECTION('',(0.,0.,-1.));
#1092=AXIS2_PLACEMENT_3D('',#1089,#1090,#1091);
#1093=CIRCLE('',#1092,10.5);
#1094=CARTESIAN_POINT('',(0.,10.4762161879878,0.706324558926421));
#1095=VERTEX_POINT('',#1094);
#1096=EDGE_CURVE('E714',#1095,#1086,#1093,.T.);
#1097=ORIENTED_EDGE('',*,*,#1096,.F.);
#1098=DIRECTION('',(0.,0.883542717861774,0.468350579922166));
#1099=VECTOR('',#1098,1.);
#1100=CARTESIAN_POINT('',(0.,8.25088105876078,-0.473286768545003));
#1101=LINE('',#1100,#1099);
#1102=EDGE_CURVE('E757',#1095,#373,#1101,.T.);
#1103=ORIENTED_EDGE('',*,*,#1102,.T.);
#1104=ORIENTED_EDGE('',*,*,#374,.F.);
#1105=DIRECTION('',(0.,0.999254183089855,-0.0386144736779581));
#1106=VECTOR('',#1105,1.);
#1107=CARTESIAN_POINT('',(0.,13.1165214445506,3.7788047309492));
#1108=LINE('',#1107,#1106);
#1109=CARTESIAN_POINT('',(0.,9.74520737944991,3.90908341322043));
#1110=VERTEX_POINT('',#1109);
#1111=EDGE_CURVE('E694',#1110,#369,#1108,.T.);
#1112=ORIENTED_EDGE('',*,*,#1111,.F.);
#1113=CARTESIAN_POINT('',(0.,0.,0.));
#1114=DIRECTION('',(-1.,0.,0.));
#1115=DIRECTION('',(0.,0.433883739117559,-0.900968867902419));
#1116=AXIS2_PLACEMENT_3D('',#1113,#1114,#1115);
#1117=CIRCLE('',#1116,10.5);
#1118=CARTESIAN_POINT('',(0.,9.13228189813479,5.18183628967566));
#1119=VERTEX_POINT('',#1118);
#1120=EDGE_CURVE('E689',#1119,#1110,#1117,.T.);
#1121=ORIENTED_EDGE('',*,*,#1120,.F.);
#1122=DIRECTION('',(0.,0.592834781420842,0.805324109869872));
#1123=VECTOR('',#1122,1.);
#1124=CARTESIAN_POINT('',(0.,6.26040419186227,1.28059359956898));
#1125=LINE('',#1124,#1123);
#1126=EDGE_CURVE('E760',#1119,#49,#1125,.T.);
#1127=ORIENTED_EDGE('',*,*,#1126,.T.);
#1128=EDGE_LOOP('',(#792,#800,#809,#815,#816,#824,#833,#839,#840,#848,#857,#863,#864,#872,#881,
#887,#888,#896,#905,#911,#912,#920,#929,#935,#936,#944,#953,#959,#960,#968,#977,#983,#984,#992,
#1001,#1007,#1008,#1016,#1025,#1031,#1032,#1040,#1049,#1055,#1056,#1064,#1073,#1079,#1080,#1088,
#1097,#1103,#1104,#1112,#1121,#1127));
#1129=FACE_BOUND('',#1128,.T.);
#1130=ORIENTED_EDGE('',*,*,#397,.T.);
#1131=EDGE_LOOP('',(#1130));
#1132=FACE_BOUND('',#1131,.T.);
#1133=ADVANCED_FACE('F797',(#1129,#1132),#791,.F.);
#1134=CARTESIAN_POINT('',(-1.2,13.4571394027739,-2.28645994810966));
#1135=DIRECTION('',(0.,-0.468350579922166,-0.883542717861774));
#1136=DIRECTION('',(0.,0.883542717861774,-0.468350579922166));
#1137=AXIS2_PLACEMENT_3D('',#1134,#1135,#1136);
#1138=PLANE('',#1137);
#1139=ORIENTED_EDGE('',*,*,#486,.F.);
#1140=DIRECTION('',(1.,0.,0.));
#1141=VECTOR('',#1140,1.);
#1142=CARTESIAN_POINT('',(-1.2,10.4762161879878,-0.706324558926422));
#1143=LINE('',#1142,#1141);
#1144=EDGE_CURVE('E729',#477,#1086,#1143,.T.);
#1145=ORIENTED_EDGE('',*,*,#1144,.T.);
#1146=ORIENTED_EDGE('',*,*,#1087,.T.);
#1147=ORIENTED_EDGE('',*,*,#782,.F.);
#1148=EDGE_LOOP('',(#1139,#1145,#1146,#1147));
#1149=FACE_BOUND('',#1148,.T.);
#1150=ADVANCED_FACE('F936',(#1149),#1138,.F.);
#1151=CARTESIAN_POINT('',(-1.2,13.4571394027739,2.28645994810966));
#1152=DIRECTION('',(0.,-0.468350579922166,0.883542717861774));
#1153=DIRECTION('',(0.,-0.883542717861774,-0.468350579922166));
#1154=AXIS2_PLACEMENT_3D('',#1151,#1152,#1153);
#1155=PLANE('',#1154);
#1156=ORIENTED_EDGE('',*,*,#1102,.F.);
#1157=DIRECTION('',(1.,0.,0.));
#1158=VECTOR('',#1157,1.);
#1159=CARTESIAN_POINT('',(-1.2,10.4762161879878,0.706324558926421));
#1160=LINE('',#1159,#1158);
#1161=EDGE_CURVE('E725',#468,#1095,#1160,.T.);
#1162=ORIENTED_EDGE('',*,*,#1161,.F.);
#1163=ORIENTED_EDGE('',*,*,#469,.F.);
#1164=ORIENTED_EDGE('',*,*,#380,.F.);
#1165=EDGE_LOOP('',(#1156,#1162,#1163,#1164));
#1166=FACE_BOUND('',#1165,.T.);
#1167=ADVANCED_FACE('F947',(#1166),#1155,.F.);
#1168=CARTESIAN_POINT('',(-1.2,0.,0.));
#1169=DIRECTION('',(1.,0.,0.));
#1170=DIRECTION('',(0.,0.,-1.));
#1171=AXIS2_PLACEMENT_3D('',#1168,#1169,#1170);
#1172=CYLINDRICAL_SURFACE('',#1171,10.5);
#1173=ORIENTED_EDGE('',*,*,#1096,.T.);
#1174=ORIENTED_EDGE('',*,*,#1144,.F.);
#1175=ORIENTED_EDGE('',*,*,#478,.F.);
#1176=ORIENTED_EDGE('',*,*,#1161,.T.);
#1177=EDGE_LOOP('',(#1173,#1174,#1175,#1176));
#1178=FACE_BOUND('',#1177,.T.);
#1179=ADVANCED_FACE('F953',(#1178),#1172,.T.);
#1180=CARTESIAN_POINT('',(-1.2,13.1165214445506,3.7788047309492));
#1181=DIRECTION('',(0.,-0.0386144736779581,-0.999254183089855));
#1182=DIRECTION('',(0.,0.999254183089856,-0.0386144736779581));
#1183=AXIS2_PLACEMENT_3D('',#1180,#1181,#1182);
#1184=PLANE('',#1183);
#1185=ORIENTED_EDGE('',*,*,#460,.F.);
#1186=DIRECTION('',(1.,0.,0.));
#1187=VECTOR('',#1186,1.);
#1188=CARTESIAN_POINT('',(-1.2,9.74520737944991,3.90908341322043));
#1189=LINE('',#1188,#1187);
#1190=EDGE_CURVE('E704',#453,#1110,#1189,.T.);
#1191=ORIENTED_EDGE('',*,*,#1190,.T.);
#1192=ORIENTED_EDGE('',*,*,#1111,.T.);
#1193=ORIENTED_EDGE('',*,*,#370,.F.);
#1194=EDGE_LOOP('',(#1185,#1191,#1192,#1193));
#1195=FACE_BOUND('',#1194,.T.);
#1196=ADVANCED_FACE('F1048',(#1195),#1184,.F.);
#1197=CARTESIAN_POINT('',(-1.2,11.1324058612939,7.89886319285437));
#1198=DIRECTION('',(0.,-0.805324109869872,0.592834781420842));
#1199=DIRECTION('',(0.,-0.592834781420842,-0.805324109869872));
#1200=AXIS2_PLACEMENT_3D('',#1197,#1198,#1199);
#1201=PLANE('',#1200);
#1202=ORIENTED_EDGE('',*,*,#1126,.F.);
#1203=DIRECTION('',(1.,0.,0.));
#1204=VECTOR('',#1203,1.);
#1205=CARTESIAN_POINT('',(-1.2,9.13228189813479,5.18183628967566));
#1206=LINE('',#1205,#1204);
#1207=EDGE_CURVE('E700',#444,#1119,#1206,.T.);
#1208=ORIENTED_EDGE('',*,*,#1207,.F.);
#1209=ORIENTED_EDGE('',*,*,#445,.F.);
#1210=ORIENTED_EDGE('',*,*,#56,.F.);
#1211=EDGE_LOOP('',(#1202,#1208,#1209,#1210));
#1212=FACE_BOUND('',#1211,.T.);
#1213=ADVANCED_FACE('F1051',(#1212),#1201,.F.);
#1214=CARTESIAN_POINT('',(-1.2,0.,0.));
#1215=DIRECTION('',(1.,0.,0.));
#1216=DIRECTION('',(0.,0.,-1.));
#1217=AXIS2_PLACEMENT_3D('',#1214,#1215,#1216);
#1218=CYLINDRICAL_SURFACE('',#1217,10.5);
#1219=ORIENTED_EDGE('',*,*,#1120,.T.);
#1220=ORIENTED_EDGE('',*,*,#1190,.F.);
#1221=ORIENTED_EDGE('',*,*,#454,.F.);
#1222=ORIENTED_EDGE('',*,*,#1207,.T.);
#1223=EDGE_LOOP('',(#1219,#1220,#1221,#1222));
#1224=FACE_BOUND('',#1223,.T.);
#1225=ADVANCED_FACE('F1043',(#1224),#1218,.T.);
#1226=CARTESIAN_POINT('',(-1.2,6.60276280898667,-11.9467997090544));
#1227=DIRECTION('',(0.,-0.982793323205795,-0.184708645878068));
#1228=DIRECTION('',(0.,0.184708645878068,-0.982793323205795));
#1229=AXIS2_PLACEMENT_3D('',#1226,#1227,#1228);
#1230=PLANE('',#1229);
#1231=ORIENTED_EDGE('',*,*,#537,.F.);
#1232=DIRECTION('',(1.,0.,0.));
#1233=VECTOR('',#1232,1.);
#1234=CARTESIAN_POINT('',(-1.2,5.97958717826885,-8.63102179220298));
#1235=LINE('',#1234,#1233);
#1236=EDGE_CURVE('E580',#530,#1038,#1235,.T.);
#1237=ORIENTED_EDGE('',*,*,#1236,.T.);
#1238=ORIENTED_EDGE('',*,*,#1039,.T.);
#1239=ORIENTED_EDGE('',*,*,#353,.F.);
#1240=EDGE_LOOP('',(#1231,#1237,#1238,#1239));
#1241=FACE_BOUND('',#1240,.T.);
#1242=ADVANCED_FACE('F1040',(#1241),#1230,.F.);
#1243=CARTESIAN_POINT('',(-1.2,10.1780155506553,-9.09563078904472));
#1244=DIRECTION('',(0.,0.398769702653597,0.917051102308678));
#1245=DIRECTION('',(0.,-0.917051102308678,0.398769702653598));
#1246=AXIS2_PLACEMENT_3D('',#1243,#1244,#1245);
#1247=PLANE('',#1246);
#1248=ORIENTED_EDGE('',*,*,#1054,.F.);
#1249=DIRECTION('',(1.,0.,0.));
#1250=VECTOR('',#1249,1.);
#1251=CARTESIAN_POINT('',(-1.2,7.08404073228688,-7.75024947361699));
#1252=LINE('',#1251,#1250);
#1253=EDGE_CURVE('E615',#521,#1047,#1252,.T.);
#1254=ORIENTED_EDGE('',*,*,#1253,.F.);
#1255=ORIENTED_EDGE('',*,*,#522,.F.);
#1256=ORIENTED_EDGE('',*,*,#326,.F.);
#1257=EDGE_LOOP('',(#1248,#1254,#1255,#1256));
#1258=FACE_BOUND('',#1257,.T.);
#1259=ADVANCED_FACE('F968',(#1258),#1247,.F.);
#1260=CARTESIAN_POINT('',(-1.2,0.,0.));
#1261=DIRECTION('',(1.,0.,0.));
#1262=DIRECTION('',(0.,0.,-1.));
#1263=AXIS2_PLACEMENT_3D('',#1260,#1261,#1262);
#1264=CYLINDRICAL_SURFACE('',#1263,10.5);
#1265=ORIENTED_EDGE('',*,*,#1048,.T.);
#1266=ORIENTED_EDGE('',*,*,#1236,.F.);
#1267=ORIENTED_EDGE('',*,*,#531,.F.);
#1268=ORIENTED_EDGE('',*,*,#1253,.T.);
#1269=EDGE_LOOP('',(#1265,#1266,#1267,#1268));
#1270=FACE_BOUND('',#1269,.T.);
#1271=ADVANCED_FACE('F972',(#1270),#1264,.T.);
#1272=CARTESIAN_POINT('',(-1.2,11.132405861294,-7.89886319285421));
#1273=DIRECTION('',(0.,-0.805324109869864,-0.592834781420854));
#1274=DIRECTION('',(0.,0.592834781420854,-0.805324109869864));
#1275=AXIS2_PLACEMENT_3D('',#1272,#1273,#1274);
#1276=PLANE('',#1275);
#1277=ORIENTED_EDGE('',*,*,#513,.F.);
#1278=DIRECTION('',(1.,0.,0.));
#1279=VECTOR('',#1278,1.);
#1280=CARTESIAN_POINT('',(-1.2,9.13228189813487,-5.18183628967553));
#1281=LINE('',#1280,#1279);
#1282=EDGE_CURVE('E600',#506,#1062,#1281,.T.);
#1283=ORIENTED_EDGE('',*,*,#1282,.T.);
#1284=ORIENTED_EDGE('',*,*,#1063,.T.);
#1285=ORIENTED_EDGE('',*,*,#316,.F.);
#1286=EDGE_LOOP('',(#1277,#1283,#1284,#1285));
#1287=FACE_BOUND('',#1286,.T.);
#1288=ADVANCED_FACE('F1033',(#1287),#1276,.F.);
#1289=CARTESIAN_POINT('',(-1.2,13.1165214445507,-3.77880473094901));
#1290=DIRECTION('',(0.,-0.0386144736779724,0.999254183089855));
#1291=DIRECTION('',(0.,-0.999254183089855,-0.0386144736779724));
#1292=AXIS2_PLACEMENT_3D('',#1289,#1290,#1291);
#1293=PLANE('',#1292);
#1294=ORIENTED_EDGE('',*,*,#1078,.F.);
#1295=DIRECTION('',(1.,0.,0.));
#1296=VECTOR('',#1295,1.);
#1297=CARTESIAN_POINT('',(-1.2,9.74520737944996,-3.90908341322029));
#1298=LINE('',#1297,#1296);
#1299=EDGE_CURVE('E595',#497,#1071,#1298,.T.);
#1300=ORIENTED_EDGE('',*,*,#1299,.F.);
#1301=ORIENTED_EDGE('',*,*,#498,.F.);
#1302=ORIENTED_EDGE('',*,*,#775,.F.);
#1303=EDGE_LOOP('',(#1294,#1300,#1301,#1302));
#1304=FACE_BOUND('',#1303,.T.);
#1305=ADVANCED_FACE('F959',(#1304),#1293,.F.);
#1306=CARTESIAN_POINT('',(-1.2,0.,0.));
#1307=DIRECTION('',(1.,0.,0.));
#1308=DIRECTION('',(0.,0.,-1.));
#1309=AXIS2_PLACEMENT_3D('',#1306,#1307,#1308);
#1310=CYLINDRICAL_SURFACE('',#1309,10.5);
#1311=ORIENTED_EDGE('',*,*,#1072,.T.);
#1312=ORIENTED_EDGE('',*,*,#1282,.F.);
#1313=ORIENTED_EDGE('',*,*,#507,.F.);
#1314=ORIENTED_EDGE('',*,*,#1299,.T.);
#1315=EDGE_LOOP('',(#1311,#1312,#1313,#1314));
#1316=FACE_BOUND('',#1315,.T.);
#1317=ADVANCED_FACE('F963',(#1316),#1310,.T.);
#1318=CARTESIAN_POINT('',(-1.2,0.765361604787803,-13.6285260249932));
#1319=DIRECTION('',(0.,-0.965608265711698,0.260001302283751));
#1320=DIRECTION('',(0.,-0.260001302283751,-0.965608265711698));
#1321=AXIS2_PLACEMENT_3D('',#1318,#1319,#1320);
#1322=PLANE('',#1321);
#1323=ORIENTED_EDGE('',*,*,#561,.F.);
#1324=DIRECTION('',(1.,0.,0.));
#1325=VECTOR('',#1324,1.);
#1326=CARTESIAN_POINT('',(-1.2,1.64256188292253,-10.3707275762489));
#1327=LINE('',#1326,#1325);
#1328=EDGE_CURVE('E544',#554,#1014,#1327,.T.);
#1329=ORIENTED_EDGE('',*,*,#1328,.T.);
#1330=ORIENTED_EDGE('',*,*,#1015,.T.);
#1331=ORIENTED_EDGE('',*,*,#299,.F.);
#1332=EDGE_LOOP('',(#1323,#1329,#1330,#1331));
#1333=FACE_BOUND('',#1332,.T.);
#1334=ADVANCED_FACE('F1028',(#1333),#1322,.F.);
#1335=CARTESIAN_POINT('',(-1.2,5.22362885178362,-12.610955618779));
#1336=DIRECTION('',(0.,0.757172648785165,0.653214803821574));
#1337=DIRECTION('',(0.,-0.653214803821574,0.757172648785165));
#1338=AXIS2_PLACEMENT_3D('',#1335,#1336,#1337);
#1339=PLANE('',#1338);
#1340=ORIENTED_EDGE('',*,*,#1030,.F.);
#1341=DIRECTION('',(1.,0.,0.));
#1342=VECTOR('',#1341,1.);
#1343=CARTESIAN_POINT('',(-1.2,3.01979293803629,-10.0563835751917));
#1344=LINE('',#1343,#1342);
#1345=EDGE_CURVE('E576',#545,#1023,#1344,.T.);
#1346=ORIENTED_EDGE('',*,*,#1345,.F.);
#1347=ORIENTED_EDGE('',*,*,#546,.F.);
#1348=ORIENTED_EDGE('',*,*,#343,.F.);
#1349=EDGE_LOOP('',(#1340,#1346,#1347,#1348));
#1350=FACE_BOUND('',#1349,.T.);
#1351=ADVANCED_FACE('F977',(#1350),#1339,.F.);
#1352=CARTESIAN_POINT('',(-1.2,0.,0.));
#1353=DIRECTION('',(1.,0.,0.));
#1354=DIRECTION('',(0.,0.,-1.));
#1355=AXIS2_PLACEMENT_3D('',#1352,#1353,#1354);
#1356=CYLINDRICAL_SURFACE('',#1355,10.5);
#1357=ORIENTED_EDGE('',*,*,#1024,.T.);
#1358=ORIENTED_EDGE('',*,*,#1328,.F.);
#1359=ORIENTED_EDGE('',*,*,#555,.F.);
#1360=ORIENTED_EDGE('',*,*,#1345,.T.);
#1361=EDGE_LOOP('',(#1357,#1358,#1359,#1360));
#1362=FACE_BOUND('',#1361,.T.);
#1363=ADVANCED_FACE('F981',(#1362),#1356,.T.);
#1364=CARTESIAN_POINT('',(-1.2,-13.1165214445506,-3.77880473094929));
#1365=DIRECTION('',(0.,0.0386144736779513,0.999254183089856));
#1366=DIRECTION('',(0.,-0.999254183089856,0.0386144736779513));
#1367=AXIS2_PLACEMENT_3D('',#1364,#1365,#1366);
#1368=PLANE('',#1367);
#1369=ORIENTED_EDGE('',*,*,#633,.F.);
#1370=DIRECTION('',(1.,0.,0.));
#1371=VECTOR('',#1370,1.);
#1372=CARTESIAN_POINT('',(-1.2,-9.74520737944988,-3.9090834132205));
#1373=LINE('',#1372,#1371);
#1374=EDGE_CURVE('E487',#626,#942,#1373,.T.);
#1375=ORIENTED_EDGE('',*,*,#1374,.T.);
#1376=ORIENTED_EDGE('',*,*,#943,.T.);
#1377=ORIENTED_EDGE('',*,*,#272,.F.);
#1378=EDGE_LOOP('',(#1369,#1375,#1376,#1377));
#1379=FACE_BOUND('',#1378,.T.);
#1380=ADVANCED_FACE('F1013',(#1379),#1368,.F.);
#1381=CARTESIAN_POINT('',(-1.2,-11.1324058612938,-7.89886319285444));
#1382=DIRECTION('',(0.,0.805324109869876,-0.592834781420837));
#1383=DIRECTION('',(0.,0.592834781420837,0.805324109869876));
#1384=AXIS2_PLACEMENT_3D('',#1381,#1382,#1383);
#1385=PLANE('',#1384);
#1386=ORIENTED_EDGE('',*,*,#958,.F.);
#1387=DIRECTION('',(1.,0.,0.));
#1388=VECTOR('',#1387,1.);
#1389=CARTESIAN_POINT('',(-1.2,-9.13228189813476,-5.18183628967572));
#1390=LINE('',#1389,#1388);
#1391=EDGE_CURVE('E559',#617,#951,#1390,.T.);
#1392=ORIENTED_EDGE('',*,*,#1391,.F.);
#1393=ORIENTED_EDGE('',*,*,#618,.F.);
#1394=ORIENTED_EDGE('',*,*,#245,.F.);
#1395=EDGE_LOOP('',(#1386,#1392,#1393,#1394));
#1396=FACE_BOUND('',#1395,.T.);
#1397=ADVANCED_FACE('F1007',(#1396),#1385,.F.);
#1398=CARTESIAN_POINT('',(-1.2,0.,0.));
#1399=DIRECTION('',(1.,0.,0.));
#1400=DIRECTION('',(0.,0.,-1.));
#1401=AXIS2_PLACEMENT_3D('',#1398,#1399,#1400);
#1402=CYLINDRICAL_SURFACE('',#1401,10.5);
#1403=ORIENTED_EDGE('',*,*,#952,.T.);
#1404=ORIENTED_EDGE('',*,*,#1374,.F.);
#1405=ORIENTED_EDGE('',*,*,#627,.F.);
#1406=ORIENTED_EDGE('',*,*,#1391,.T.);
#1407=EDGE_LOOP('',(#1403,#1404,#1405,#1406));
#1408=FACE_BOUND('',#1407,.T.);
#1409=ADVANCED_FACE('F1010',(#1408),#1402,.T.);
#1410=CARTESIAN_POINT('',(-1.2,-10.1780155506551,-9.09563078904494));
#1411=DIRECTION('',(0.,-0.398769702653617,0.91705110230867));
#1412=DIRECTION('',(0.,-0.91705110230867,-0.398769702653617));
#1413=AXIS2_PLACEMENT_3D('',#1410,#1411,#1412);
#1414=PLANE('',#1413);
#1415=ORIENTED_EDGE('',*,*,#609,.F.);
#1416=DIRECTION('',(1.,0.,0.));
#1417=VECTOR('',#1416,1.);
#1418=CARTESIAN_POINT('',(-1.2,-7.08404073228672,-7.75024947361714));
#1419=LINE('',#1418,#1417);
#1420=EDGE_CURVE('E525',#602,#966,#1419,.T.);
#1421=ORIENTED_EDGE('',*,*,#1420,.T.);
#1422=ORIENTED_EDGE('',*,*,#967,.T.);
#1423=ORIENTED_EDGE('',*,*,#235,.F.);
#1424=EDGE_LOOP('',(#1415,#1421,#1422,#1423));
#1425=FACE_BOUND('',#1424,.T.);
#1426=ADVANCED_FACE('F1026',(#1425),#1414,.F.);
#1427=CARTESIAN_POINT('',(-1.2,-6.60276280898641,-11.9467997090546));
#1428=DIRECTION('',(0.,0.982793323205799,-0.184708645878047));
#1429=DIRECTION('',(0.,0.184708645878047,0.982793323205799));
#1430=AXIS2_PLACEMENT_3D('',#1427,#1428,#1429);
#1431=PLANE('',#1430);
#1432=ORIENTED_EDGE('',*,*,#982,.F.);
#1433=DIRECTION('',(1.,0.,0.));
#1434=VECTOR('',#1433,1.);
#1435=CARTESIAN_POINT('',(-1.2,-5.97958717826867,-8.63102179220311));
#1436=LINE('',#1435,#1434);
#1437=EDGE_CURVE('E519',#593,#975,#1436,.T.);
#1438=ORIENTED_EDGE('',*,*,#1437,.F.);
#1439=ORIENTED_EDGE('',*,*,#594,.F.);
#1440=ORIENTED_EDGE('',*,*,#218,.F.);
#1441=EDGE_LOOP('',(#1432,#1438,#1439,#1440));
#1442=FACE_BOUND('',#1441,.T.);
#1443=ADVANCED_FACE('F997',(#1442),#1431,.F.);
#1444=CARTESIAN_POINT('',(-1.2,0.,0.));
#1445=DIRECTION('',(1.,0.,0.));
#1446=DIRECTION('',(0.,0.,-1.));
#1447=AXIS2_PLACEMENT_3D('',#1444,#1445,#1446);
#1448=CYLINDRICAL_SURFACE('',#1447,10.5);
#1449=ORIENTED_EDGE('',*,*,#976,.T.);
#1450=ORIENTED_EDGE('',*,*,#1420,.F.);
#1451=ORIENTED_EDGE('',*,*,#603,.F.);
#1452=ORIENTED_EDGE('',*,*,#1437,.T.);
#1453=EDGE_LOOP('',(#1449,#1450,#1451,#1452));
#1454=FACE_BOUND('',#1453,.T.);
#1455=ADVANCED_FACE('F1001',(#1454),#1448,.T.);
#1456=CARTESIAN_POINT('',(-1.2,-5.22362885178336,-12.6109556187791));
#1457=DIRECTION('',(0.,-0.757172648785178,0.653214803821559));
#1458=DIRECTION('',(0.,-0.653214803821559,-0.757172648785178));
#1459=AXIS2_PLACEMENT_3D('',#1456,#1457,#1458);
#1460=PLANE('',#1459);
#1461=ORIENTED_EDGE('',*,*,#585,.F.);
#1462=DIRECTION('',(1.,0.,0.));
#1463=VECTOR('',#1462,1.);
#1464=CARTESIAN_POINT('',(-1.2,-3.01979293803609,-10.0563835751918));
#1465=LINE('',#1464,#1463);
#1466=EDGE_CURVE('E523',#578,#990,#1465,.T.);
#1467=ORIENTED_EDGE('',*,*,#1466,.T.);
#1468=ORIENTED_EDGE('',*,*,#991,.T.);
#1469=ORIENTED_EDGE('',*,*,#208,.F.);
#1470=EDGE_LOOP('',(#1461,#1467,#1468,#1469));
#1471=FACE_BOUND('',#1470,.T.);
#1472=ADVANCED_FACE('F1162',(#1471),#1460,.F.);
#1473=CARTESIAN_POINT('',(-1.2,-0.765361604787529,-13.6285260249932));
#1474=DIRECTION('',(0.,0.965608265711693,0.260001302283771));
#1475=DIRECTION('',(0.,-0.260001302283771,0.965608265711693));
#1476=AXIS2_PLACEMENT_3D('',#1473,#1474,#1475);
#1477=PLANE('',#1476);
#1478=ORIENTED_EDGE('',*,*,#1006,.F.);
#1479=DIRECTION('',(1.,0.,0.));
#1480=VECTOR('',#1479,1.);
#1481=CARTESIAN_POINT('',(-1.2,-1.64256188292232,-10.370727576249));
#1482=LINE('',#1481,#1480);
#1483=EDGE_CURVE('E540',#569,#999,#1482,.T.);
#1484=ORIENTED_EDGE('',*,*,#1483,.F.);
#1485=ORIENTED_EDGE('',*,*,#570,.F.);
#1486=ORIENTED_EDGE('',*,*,#289,.F.);
#1487=EDGE_LOOP('',(#1478,#1484,#1485,#1486));
#1488=FACE_BOUND('',#1487,.T.);
#1489=ADVANCED_FACE('F987',(#1488),#1477,.F.);
#1490=CARTESIAN_POINT('',(-1.2,0.,0.));
#1491=DIRECTION('',(1.,0.,0.));
#1492=DIRECTION('',(0.,0.,-1.));
#1493=AXIS2_PLACEMENT_3D('',#1490,#1491,#1492);
#1494=CYLINDRICAL_SURFACE('',#1493,10.5);
#1495=ORIENTED_EDGE('',*,*,#1000,.T.);
#1496=ORIENTED_EDGE('',*,*,#1466,.F.);
#1497=ORIENTED_EDGE('',*,*,#579,.F.);
#1498=ORIENTED_EDGE('',*,*,#1483,.T.);
#1499=EDGE_LOOP('',(#1495,#1496,#1497,#1498));
#1500=FACE_BOUND('',#1499,.T.);
#1501=ADVANCED_FACE('F991',(#1500),#1494,.T.);
#1502=CARTESIAN_POINT('',(-1.2,-6.60276280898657,11.9467997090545));
#1503=DIRECTION('',(0.,0.982793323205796,0.184708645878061));
#1504=DIRECTION('',(0.,-0.184708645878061,0.982793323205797));
#1505=AXIS2_PLACEMENT_3D('',#1502,#1503,#1504);
#1506=PLANE('',#1505);
#1507=ORIENTED_EDGE('',*,*,#705,.F.);
#1508=DIRECTION('',(1.,0.,0.));
#1509=VECTOR('',#1508,1.);
#1510=CARTESIAN_POINT('',(-1.2,-5.97958717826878,8.63102179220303));
#1511=LINE('',#1510,#1509);
#1512=EDGE_CURVE('E447',#698,#870,#1511,.T.);
#1513=ORIENTED_EDGE('',*,*,#1512,.T.);
#1514=ORIENTED_EDGE('',*,*,#871,.T.);
#1515=ORIENTED_EDGE('',*,*,#191,.F.);
#1516=EDGE_LOOP('',(#1507,#1513,#1514,#1515));
#1517=FACE_BOUND('',#1516,.T.);
#1518=ADVANCED_FACE('F1186',(#1517),#1506,.F.);
#1519=CARTESIAN_POINT('',(-1.2,-10.1780155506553,9.0956307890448));
#1520=DIRECTION('',(0.,-0.398769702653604,-0.917051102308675));
#1521=DIRECTION('',(0.,0.917051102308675,-0.398769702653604));
#1522=AXIS2_PLACEMENT_3D('',#1519,#1520,#1521);
#1523=PLANE('',#1522);
#1524=ORIENTED_EDGE('',*,*,#886,.F.);
#1525=DIRECTION('',(1.,0.,0.));
#1526=VECTOR('',#1525,1.);
#1527=CARTESIAN_POINT('',(-1.2,-7.08404073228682,7.75024947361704));
#1528=LINE('',#1527,#1526);
#1529=EDGE_CURVE('E502',#689,#879,#1528,.T.);
#1530=ORIENTED_EDGE('',*,*,#1529,.F.);
#1531=ORIENTED_EDGE('',*,*,#690,.F.);
#1532=ORIENTED_EDGE('',*,*,#164,.F.);
#1533=EDGE_LOOP('',(#1524,#1530,#1531,#1532));
#1534=FACE_BOUND('',#1533,.T.);
#1535=ADVANCED_FACE('F856',(#1534),#1523,.F.);
#1536=CARTESIAN_POINT('',(-1.2,0.,0.));
#1537=DIRECTION('',(1.,0.,0.));
#1538=DIRECTION('',(0.,0.,-1.));
#1539=AXIS2_PLACEMENT_3D('',#1536,#1537,#1538);
#1540=CYLINDRICAL_SURFACE('',#1539,10.5);
#1541=ORIENTED_EDGE('',*,*,#880,.T.);
#1542=ORIENTED_EDGE('',*,*,#1512,.F.);
#1543=ORIENTED_EDGE('',*,*,#699,.F.);
#1544=ORIENTED_EDGE('',*,*,#1529,.T.);
#1545=EDGE_LOOP('',(#1541,#1542,#1543,#1544));
#1546=FACE_BOUND('',#1545,.T.);
#1547=ADVANCED_FACE('F859',(#1546),#1540,.T.);
#1548=CARTESIAN_POINT('',(-1.2,-11.1324058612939,7.89886319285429));
#1549=DIRECTION('',(0.,0.805324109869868,0.592834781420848));
#1550=DIRECTION('',(0.,-0.592834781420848,0.805324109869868));
#1551=AXIS2_PLACEMENT_3D('',#1548,#1549,#1550);
#1552=PLANE('',#1551);
#1553=ORIENTED_EDGE('',*,*,#681,.F.);
#1554=DIRECTION('',(1.,0.,0.));
#1555=VECTOR('',#1554,1.);
#1556=CARTESIAN_POINT('',(-1.2,-9.13228189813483,5.18183628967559));
#1557=LINE('',#1556,#1555);
#1558=EDGE_CURVE('E468',#674,#894,#1557,.T.);
#1559=ORIENTED_EDGE('',*,*,#1558,.T.);
#1560=ORIENTED_EDGE('',*,*,#895,.T.);
#1561=ORIENTED_EDGE('',*,*,#154,.F.);
#1562=EDGE_LOOP('',(#1553,#1559,#1560,#1561));
#1563=FACE_BOUND('',#1562,.T.);
#1564=ADVANCED_FACE('F910',(#1563),#1552,.F.);
#1565=CARTESIAN_POINT('',(-1.2,-13.1165214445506,3.77880473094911));
#1566=DIRECTION('',(0.,0.0386144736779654,-0.999254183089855));
#1567=DIRECTION('',(0.,0.999254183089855,0.0386144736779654));
#1568=AXIS2_PLACEMENT_3D('',#1565,#1566,#1567);
#1569=PLANE('',#1568);
#1570=ORIENTED_EDGE('',*,*,#910,.F.);
#1571=DIRECTION('',(1.,0.,0.));
#1572=VECTOR('',#1571,1.);
#1573=CARTESIAN_POINT('',(-1.2,-9.74520737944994,3.90908341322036));
#1574=LINE('',#1573,#1572);
#1575=EDGE_CURVE('E462',#665,#903,#1574,.T.);
#1576=ORIENTED_EDGE('',*,*,#1575,.F.);
#1577=ORIENTED_EDGE('',*,*,#666,.F.);
#1578=ORIENTED_EDGE('',*,*,#137,.F.);
#1579=EDGE_LOOP('',(#1570,#1576,#1577,#1578));
#1580=FACE_BOUND('',#1579,.T.);
#1581=ADVANCED_FACE('F905',(#1580),#1569,.F.);
#1582=CARTESIAN_POINT('',(-1.2,0.,0.));
#1583=DIRECTION('',(1.,0.,0.));
#1584=DIRECTION('',(0.,0.,-1.));
#1585=AXIS2_PLACEMENT_3D('',#1582,#1583,#1584);
#1586=CYLINDRICAL_SURFACE('',#1585,10.5);
#1587=ORIENTED_EDGE('',*,*,#904,.T.);
#1588=ORIENTED_EDGE('',*,*,#1558,.F.);
#1589=ORIENTED_EDGE('',*,*,#675,.F.);
#1590=ORIENTED_EDGE('',*,*,#1575,.T.);
#1591=EDGE_LOOP('',(#1587,#1588,#1589,#1590));
#1592=FACE_BOUND('',#1591,.T.);
#1593=ADVANCED_FACE('F907',(#1592),#1586,.T.);
#1594=CARTESIAN_POINT('',(-1.2,-13.4571394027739,2.28645994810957));
#1595=DIRECTION('',(0.,0.46835057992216,0.883542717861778));
#1596=DIRECTION('',(0.,-0.883542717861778,0.46835057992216));
#1597=AXIS2_PLACEMENT_3D('',#1594,#1595,#1596);
#1598=PLANE('',#1597);
#1599=ORIENTED_EDGE('',*,*,#657,.F.);
#1600=DIRECTION('',(1.,0.,0.));
#1601=VECTOR('',#1600,1.);
#1602=CARTESIAN_POINT('',(-1.2,-10.4762161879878,0.706324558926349));
#1603=LINE('',#1602,#1601);
#1604=EDGE_CURVE('E466',#650,#918,#1603,.T.);
#1605=ORIENTED_EDGE('',*,*,#1604,.T.);
#1606=ORIENTED_EDGE('',*,*,#919,.T.);
#1607=ORIENTED_EDGE('',*,*,#127,.F.);
#1608=EDGE_LOOP('',(#1599,#1605,#1606,#1607));
#1609=FACE_BOUND('',#1608,.T.);
#1610=ADVANCED_FACE('F1227',(#1609),#1598,.F.);
#1611=CARTESIAN_POINT('',(-1.2,-13.4571394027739,-2.28645994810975));
#1612=DIRECTION('',(0.,0.468350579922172,-0.883542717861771));
#1613=DIRECTION('',(0.,0.883542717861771,0.468350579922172));
#1614=AXIS2_PLACEMENT_3D('',#1611,#1612,#1613);
#1615=PLANE('',#1614);
#1616=ORIENTED_EDGE('',*,*,#934,.F.);
#1617=DIRECTION('',(1.,0.,0.));
#1618=VECTOR('',#1617,1.);
#1619=CARTESIAN_POINT('',(-1.2,-10.4762161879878,-0.706324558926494));
#1620=LINE('',#1619,#1618);
#1621=EDGE_CURVE('E483',#641,#927,#1620,.T.);
#1622=ORIENTED_EDGE('',*,*,#1621,.F.);
#1623=ORIENTED_EDGE('',*,*,#642,.F.);
#1624=ORIENTED_EDGE('',*,*,#262,.F.);
#1625=EDGE_LOOP('',(#1616,#1622,#1623,#1624));
#1626=FACE_BOUND('',#1625,.T.);
#1627=ADVANCED_FACE('F893',(#1626),#1615,.F.);
#1628=CARTESIAN_POINT('',(-1.2,0.,0.));
#1629=DIRECTION('',(1.,0.,0.));
#1630=DIRECTION('',(0.,0.,-1.));
#1631=AXIS2_PLACEMENT_3D('',#1628,#1629,#1630);
#1632=CYLINDRICAL_SURFACE('',#1631,10.5);
#1633=ORIENTED_EDGE('',*,*,#928,.T.);
#1634=ORIENTED_EDGE('',*,*,#1604,.F.);
#1635=ORIENTED_EDGE('',*,*,#651,.F.);
#1636=ORIENTED_EDGE('',*,*,#1621,.T.);
#1637=EDGE_LOOP('',(#1633,#1634,#1635,#1636));
#1638=FACE_BOUND('',#1637,.T.);
#1639=ADVANCED_FACE('F898',(#1638),#1632,.T.);
#1640=CARTESIAN_POINT('',(-1.2,-0.765361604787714,13.6285260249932));
#1641=DIRECTION('',(0.,0.965608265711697,-0.260001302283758));
#1642=DIRECTION('',(0.,0.260001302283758,0.965608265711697));
#1643=AXIS2_PLACEMENT_3D('',#1640,#1641,#1642);
#1644=PLANE('',#1643);
#1645=ORIENTED_EDGE('',*,*,#729,.F.);
#1646=DIRECTION('',(1.,0.,0.));
#1647=VECTOR('',#1646,1.);
#1648=CARTESIAN_POINT('',(-1.2,-1.64256188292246,10.3707275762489));
#1649=LINE('',#1648,#1647);
#1650=EDGE_CURVE('E428',#722,#846,#1649,.T.);
#1651=ORIENTED_EDGE('',*,*,#1650,.T.);
#1652=ORIENTED_EDGE('',*,*,#847,.T.);
#1653=ORIENTED_EDGE('',*,*,#110,.F.);
#1654=EDGE_LOOP('',(#1645,#1651,#1652,#1653));
#1655=FACE_BOUND('',#1654,.T.);
#1656=ADVANCED_FACE('F1251',(#1655),#1644,.F.);
#1657=CARTESIAN_POINT('',(-1.2,-5.22362885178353,12.610955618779));
#1658=DIRECTION('',(0.,-0.757172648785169,-0.653214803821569));
#1659=DIRECTION('',(0.,0.653214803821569,-0.757172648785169));
#1660=AXIS2_PLACEMENT_3D('',#1657,#1658,#1659);
#1661=PLANE('',#1660);
#1662=ORIENTED_EDGE('',*,*,#862,.F.);
#1663=DIRECTION('',(1.,0.,0.));
#1664=VECTOR('',#1663,1.);
#1665=CARTESIAN_POINT('',(-1.2,-3.01979293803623,10.0563835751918));
#1666=LINE('',#1665,#1664);
#1667=EDGE_CURVE('E443',#713,#855,#1666,.T.);
#1668=ORIENTED_EDGE('',*,*,#1667,.F.);
#1669=ORIENTED_EDGE('',*,*,#714,.F.);
#1670=ORIENTED_EDGE('',*,*,#181,.F.);
#1671=EDGE_LOOP('',(#1662,#1668,#1669,#1670));
#1672=FACE_BOUND('',#1671,.T.);
#1673=ADVANCED_FACE('F1260',(#1672),#1661,.F.);
#1674=CARTESIAN_POINT('',(-1.2,0.,0.));
#1675=DIRECTION('',(1.,0.,0.));
#1676=DIRECTION('',(0.,0.,-1.));
#1677=AXIS2_PLACEMENT_3D('',#1674,#1675,#1676);
#1678=CYLINDRICAL_SURFACE('',#1677,10.5);
#1679=ORIENTED_EDGE('',*,*,#856,.T.);
#1680=ORIENTED_EDGE('',*,*,#1650,.F.);
#1681=ORIENTED_EDGE('',*,*,#723,.F.);
#1682=ORIENTED_EDGE('',*,*,#1667,.T.);
#1683=EDGE_LOOP('',(#1679,#1680,#1681,#1682));
#1684=FACE_BOUND('',#1683,.T.);
#1685=ADVANCED_FACE('F1270',(#1684),#1678,.T.);
#1686=CARTESIAN_POINT('',(-1.2,5.22362885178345,12.6109556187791));
#1687=DIRECTION('',(0.,0.757172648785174,-0.653214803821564));
#1688=DIRECTION('',(0.,0.653214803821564,0.757172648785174));
#1689=AXIS2_PLACEMENT_3D('',#1686,#1687,#1688);
#1690=PLANE('',#1689);
#1691=ORIENTED_EDGE('',*,*,#753,.F.);
#1692=DIRECTION('',(1.,0.,0.));
#1693=VECTOR('',#1692,1.);
#1694=CARTESIAN_POINT('',(-1.2,3.01979293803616,10.0563835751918));
#1695=LINE('',#1694,#1693);
#1696=EDGE_CURVE('E411',#746,#822,#1695,.T.);
#1697=ORIENTED_EDGE('',*,*,#1696,.T.);
#1698=ORIENTED_EDGE('',*,*,#823,.T.);
#1699=ORIENTED_EDGE('',*,*,#83,.F.);
#1700=EDGE_LOOP('',(#1691,#1697,#1698,#1699));
#1701=FACE_BOUND('',#1700,.T.);
#1702=ADVANCED_FACE('F1279',(#1701),#1690,.F.);
#1703=CARTESIAN_POINT('',(-1.2,0.765361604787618,13.6285260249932));
#1704=DIRECTION('',(0.,-0.965608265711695,-0.260001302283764));
#1705=DIRECTION('',(0.,0.260001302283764,-0.965608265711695));
#1706=AXIS2_PLACEMENT_3D('',#1703,#1704,#1705);
#1707=PLANE('',#1706);
#1708=ORIENTED_EDGE('',*,*,#838,.F.);
#1709=DIRECTION('',(1.,0.,0.));
#1710=VECTOR('',#1709,1.);
#1711=CARTESIAN_POINT('',(-1.2,1.64256188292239,10.370727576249));
#1712=LINE('',#1711,#1710);
#1713=EDGE_CURVE('E424',#737,#831,#1712,.T.);
#1714=ORIENTED_EDGE('',*,*,#1713,.F.);
#1715=ORIENTED_EDGE('',*,*,#738,.F.);
#1716=ORIENTED_EDGE('',*,*,#100,.F.);
#1717=EDGE_LOOP('',(#1708,#1714,#1715,#1716));
#1718=FACE_BOUND('',#1717,.T.);
#1719=ADVANCED_FACE('F1289',(#1718),#1707,.F.);
#1720=CARTESIAN_POINT('',(-1.2,0.,0.));
#1721=DIRECTION('',(1.,0.,0.));
#1722=DIRECTION('',(0.,0.,-1.));
#1723=AXIS2_PLACEMENT_3D('',#1720,#1721,#1722);
#1724=CYLINDRICAL_SURFACE('',#1723,10.5);
#1725=ORIENTED_EDGE('',*,*,#832,.T.);
#1726=ORIENTED_EDGE('',*,*,#1696,.F.);
#1727=ORIENTED_EDGE('',*,*,#747,.F.);
#1728=ORIENTED_EDGE('',*,*,#1713,.T.);
#1729=EDGE_LOOP('',(#1725,#1726,#1727,#1728));
#1730=FACE_BOUND('',#1729,.T.);
#1731=ADVANCED_FACE('F1299',(#1730),#1724,.T.);
#1732=CARTESIAN_POINT('',(-1.2,10.1780155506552,9.09563078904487));
#1733=DIRECTION('',(0.,0.398769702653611,-0.917051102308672));
#1734=DIRECTION('',(0.,0.917051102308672,0.398769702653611));
#1735=AXIS2_PLACEMENT_3D('',#1732,#1733,#1734);
#1736=PLANE('',#1735);
#1737=ORIENTED_EDGE('',*,*,#436,.F.);
#1738=DIRECTION('',(1.,0.,0.));
#1739=VECTOR('',#1738,1.);
#1740=CARTESIAN_POINT('',(-1.2,7.08404073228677,7.75024947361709));
#1741=LINE('',#1740,#1739);
#1742=EDGE_CURVE('E390',#429,#798,#1741,.T.);
#1743=ORIENTED_EDGE('',*,*,#1742,.T.);
#1744=ORIENTED_EDGE('',*,*,#799,.T.);
#1745=ORIENTED_EDGE('',*,*,#41,.F.);
#1746=EDGE_LOOP('',(#1737,#1743,#1744,#1745));
#1747=FACE_BOUND('',#1746,.T.);
#1748=ADVANCED_FACE('F1308',(#1747),#1736,.F.);
#1749=CARTESIAN_POINT('',(-1.2,6.60276280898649,11.9467997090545));
#1750=DIRECTION('',(0.,-0.982793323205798,0.184708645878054));
#1751=DIRECTION('',(0.,-0.184708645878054,-0.982793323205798));
#1752=AXIS2_PLACEMENT_3D('',#1749,#1750,#1751);
#1753=PLANE('',#1752);
#1754=ORIENTED_EDGE('',*,*,#814,.F.);
#1755=DIRECTION('',(1.,0.,0.));
#1756=VECTOR('',#1755,1.);
#1757=CARTESIAN_POINT('',(-1.2,5.97958717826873,8.63102179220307));
#1758=LINE('',#1757,#1756);
#1759=EDGE_CURVE('E382',#427,#807,#1758,.T.);
#1760=ORIENTED_EDGE('',*,*,#1759,.F.);
#1761=ORIENTED_EDGE('',*,*,#760,.F.);
#1762=ORIENTED_EDGE('',*,*,#73,.F.);
#1763=EDGE_LOOP('',(#1754,#1760,#1761,#1762));
#1764=FACE_BOUND('',#1763,.T.);
#1765=ADVANCED_FACE('F384',(#1764),#1753,.F.);
#1766=CARTESIAN_POINT('',(-1.2,0.,0.));
#1767=DIRECTION('',(1.,0.,0.));
#1768=DIRECTION('',(0.,0.,-1.));
#1769=AXIS2_PLACEMENT_3D('',#1766,#1767,#1768);
#1770=CYLINDRICAL_SURFACE('',#1769,10.5);
#1771=ORIENTED_EDGE('',*,*,#808,.T.);
#1772=ORIENTED_EDGE('',*,*,#1742,.F.);
#1773=ORIENTED_EDGE('',*,*,#430,.F.);
#1774=ORIENTED_EDGE('',*,*,#1759,.T.);
#1775=EDGE_LOOP('',(#1771,#1772,#1773,#1774));
#1776=FACE_BOUND('',#1775,.T.);
#1777=ADVANCED_FACE('F395',(#1776),#1770,.T.);
#1778=CLOSED_SHELL('',(#60,#87,#114,#141,#168,#195,#222,#249,#276,#303,#330,#357,#384,#412,#764,
#786,#1133,#1150,#1167,#1179,#1196,#1213,#1225,#1242,#1259,#1271,#1288,#1305,#1317,#1334,#1351,
#1363,#1380,#1397,#1409,#1426,#1443,#1455,#1472,#1489,#1501,#1518,#1535,#1547,#1564,#1581,#1593,
#1610,#1627,#1639,#1656,#1673,#1685,#1702,#1719,#1731,#1748,#1765,#1777));
#1779=MANIFOLD_SOLID_BREP('B2',#1778);
#1780=ADVANCED_BREP_SHAPE_REPRESENTATION('',(#18,#1779),#14);
#1781=SHAPE_DEFINITION_REPRESENTATION(#9,#1780);
ENDSEC;
END-ISO-10303-21;
